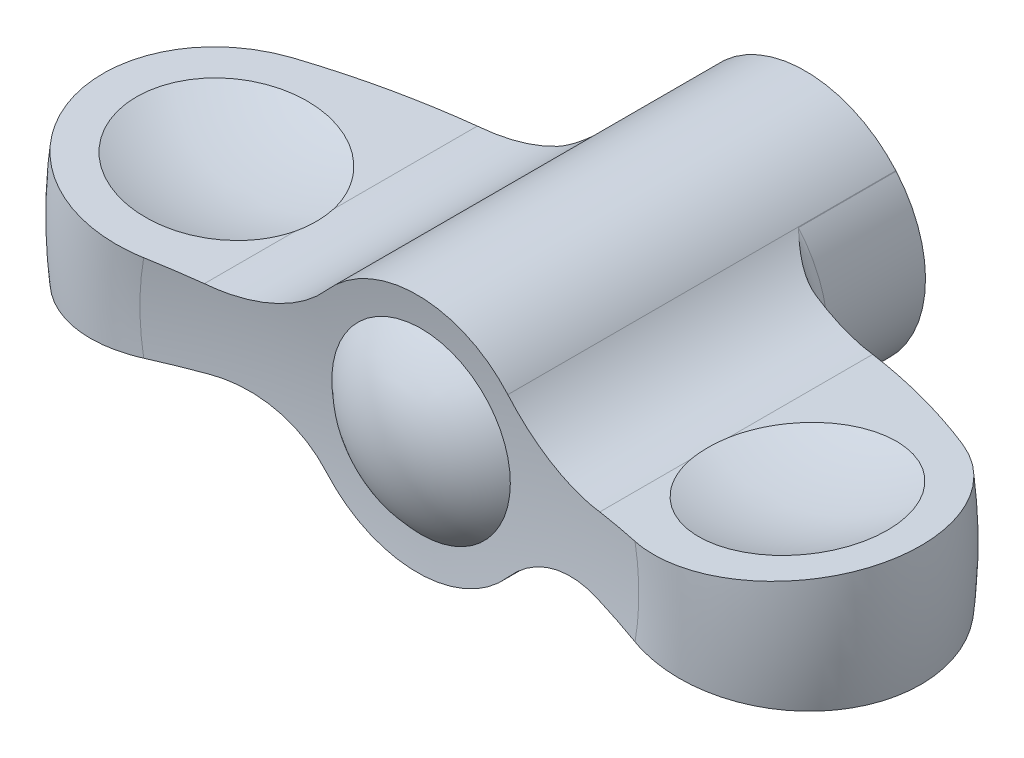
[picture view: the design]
ISO-10303-21;
HEADER;
FILE_DESCRIPTION(('STEP AP214'),'2;1');
FILE_NAME('part.step','',(''),(''),'','','');
FILE_SCHEMA(('AUTOMOTIVE_DESIGN { 1 0 10303 214 1 1 1 1 }'));
ENDSEC;
DATA;
#1=APPLICATION_CONTEXT('core data for automotive mechanical design processes');
#2=APPLICATION_PROTOCOL_DEFINITION('international standard','automotive_design',2000,#1);
#3=PRODUCT_CONTEXT('',#1,'mechanical');
#4=PRODUCT('Part','Part','',(#3));
#5=PRODUCT_RELATED_PRODUCT_CATEGORY('part','',(#4));
#6=PRODUCT_DEFINITION_FORMATION('','',#4);
#7=PRODUCT_DEFINITION_CONTEXT('part definition',#1,'design');
#8=PRODUCT_DEFINITION('design','',#6,#7);
#9=PRODUCT_DEFINITION_SHAPE('','',#8);
#10=(LENGTH_UNIT() NAMED_UNIT(*) SI_UNIT(.MILLI.,.METRE.));
#11=(NAMED_UNIT(*) PLANE_ANGLE_UNIT() SI_UNIT($,.RADIAN.));
#12=(NAMED_UNIT(*) SI_UNIT($,.STERADIAN.) SOLID_ANGLE_UNIT());
#13=UNCERTAINTY_MEASURE_WITH_UNIT(LENGTH_MEASURE(1.E-05),#10,'distance_accuracy_value','');
#14=(GEOMETRIC_REPRESENTATION_CONTEXT(3) GLOBAL_UNCERTAINTY_ASSIGNED_CONTEXT((#13)) GLOBAL_UNIT_ASSIGNED_CONTEXT((#10,
#11,#12)) REPRESENTATION_CONTEXT('',''));
#15=CARTESIAN_POINT('',(0.,0.,0.));
#16=DIRECTION('',(0.,0.,1.));
#17=DIRECTION('',(1.,0.,0.));
#18=AXIS2_PLACEMENT_3D('',#15,#16,#17);
#19=CARTESIAN_POINT('',(0.,0.,6.5));
#20=DIRECTION('',(0.,0.,1.));
#21=DIRECTION('',(0.,-1.,0.));
#22=AXIS2_PLACEMENT_3D('',#19,#20,#21);
#23=TOROIDAL_SURFACE('',#22,9.4,1.40000000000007);
#24=DIRECTION('',(0.,0.,1.));
#25=VECTOR('',#24,1.);
#26=CARTESIAN_POINT('',(6.03890778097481,-5.2470556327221,-7.02196379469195));
#27=LINE('',#26,#25);
#28=CARTESIAN_POINT('',(6.03890778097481,-5.24705563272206,6.5));
#29=VERTEX_POINT('',#28);
#30=CARTESIAN_POINT('',(6.03890778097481,-5.2470556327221,6.5021200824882));
#31=VERTEX_POINT('',#30);
#32=EDGE_CURVE('E174',#29,#31,#27,.T.);
#33=ORIENTED_EDGE('',*,*,#32,.F.);
#34=CARTESIAN_POINT('',(0.,0.,6.5));
#35=DIRECTION('',(0.,0.,1.));
#36=DIRECTION('',(0.,-1.,0.));
#37=AXIS2_PLACEMENT_3D('',#34,#35,#36);
#38=CIRCLE('',#37,8.);
#39=CARTESIAN_POINT('',(6.0470062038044,5.23772049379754,6.4999999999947));
#40=VERTEX_POINT('',#39);
#41=EDGE_CURVE('E415',#29,#40,#38,.T.);
#42=ORIENTED_EDGE('',*,*,#41,.T.);
#43=CARTESIAN_POINT('',(8.59708199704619,3.29504177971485,7.88661989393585));
#44=CARTESIAN_POINT('',(8.50944178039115,3.33729136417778,7.87729621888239));
#45=CARTESIAN_POINT('',(8.42307614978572,3.38091432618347,7.86348310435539));
#46=CARTESIAN_POINT('',(8.25334791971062,3.47048341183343,7.82827393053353));
#47=CARTESIAN_POINT('',(8.16997966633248,3.51642472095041,7.80689307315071));
#48=CARTESIAN_POINT('',(8.006927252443,3.6100455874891,7.75806975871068));
#49=CARTESIAN_POINT('',(7.92722117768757,3.65771052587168,7.73067131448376));
#50=CARTESIAN_POINT('',(7.77086822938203,3.75487699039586,7.67078020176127));
#51=CARTESIAN_POINT('',(7.69422278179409,3.80437935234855,7.6382851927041));
#52=CARTESIAN_POINT('',(7.51481068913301,3.9245724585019,7.55570149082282));
#53=CARTESIAN_POINT('',(7.41345025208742,3.996030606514,7.50367899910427));
#54=CARTESIAN_POINT('',(7.21620642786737,4.14190058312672,7.39355525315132));
#55=CARTESIAN_POINT('',(7.12032815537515,4.21631506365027,7.33544846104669));
#56=CARTESIAN_POINT('',(6.89765495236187,4.39723051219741,7.19147911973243));
#57=CARTESIAN_POINT('',(6.77323076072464,4.50501816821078,7.10356810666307));
#58=CARTESIAN_POINT('',(6.57394920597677,4.68848676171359,6.95337103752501));
#59=CARTESIAN_POINT('',(6.49659267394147,4.7626588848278,6.89250585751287));
#60=CARTESIAN_POINT('',(6.37240043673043,4.8865809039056,6.79132557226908));
#61=CARTESIAN_POINT('',(6.32451434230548,4.93561192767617,6.75141880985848));
#62=CARTESIAN_POINT('',(6.24744938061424,5.01656740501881,6.68590586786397));
#63=CARTESIAN_POINT('',(6.21784284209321,5.04817964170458,6.66041557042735));
#64=CARTESIAN_POINT('',(6.1701203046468,5.09997024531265,6.61881307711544));
#65=CARTESIAN_POINT('',(6.15183084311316,5.12002285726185,6.60274326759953));
#66=CARTESIAN_POINT('',(6.12231217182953,5.15271930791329,6.57655539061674));
#67=CARTESIAN_POINT('',(6.11100884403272,5.16531979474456,6.56646663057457));
#68=CARTESIAN_POINT('',(6.09275021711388,5.18580384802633,6.549990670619));
#69=CARTESIAN_POINT('',(6.08575717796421,5.19368060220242,6.54363714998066));
#70=CARTESIAN_POINT('',(6.07446460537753,5.20645064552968,6.53319636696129));
#71=CARTESIAN_POINT('',(6.07013806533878,5.21135545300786,6.52915239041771));
#72=CARTESIAN_POINT('',(6.06316395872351,5.21928103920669,6.52242537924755));
#73=CARTESIAN_POINT('',(6.06049083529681,5.22232358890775,6.51979601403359));
#74=CARTESIAN_POINT('',(6.05620285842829,5.22721145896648,6.51533355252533));
#75=CARTESIAN_POINT('',(6.05455913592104,5.22908696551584,6.51356171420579));
#76=CARTESIAN_POINT('',(6.05194270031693,5.23207504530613,6.51046552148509));
#77=CARTESIAN_POINT('',(6.05093886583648,5.23322217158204,6.50920550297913));
#78=CARTESIAN_POINT('',(6.04952852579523,5.23483466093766,6.50714224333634));
#79=CARTESIAN_POINT('',(6.04907130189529,5.23535757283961,6.50641962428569));
#80=CARTESIAN_POINT('',(6.04823146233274,5.23631829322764,6.50488003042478));
#81=CARTESIAN_POINT('',(6.04784824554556,5.23675678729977,6.50406390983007));
#82=CARTESIAN_POINT('',(6.04743475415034,5.2372299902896,6.50282878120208));
#83=CARTESIAN_POINT('',(6.04733123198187,5.23734847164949,6.50246832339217));
#84=CARTESIAN_POINT('',(6.04716301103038,5.23754100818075,6.50172769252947));
#85=CARTESIAN_POINT('',(6.04709815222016,5.23761524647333,6.50134760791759));
#86=CARTESIAN_POINT('',(6.04703697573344,5.23768527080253,6.50077037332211));
#87=CARTESIAN_POINT('',(6.04702259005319,5.23770173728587,6.50057747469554));
#88=CARTESIAN_POINT('',(6.0470060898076,5.23772062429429,6.50018965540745));
#89=CARTESIAN_POINT('',(6.04700402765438,5.23772298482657,6.49999472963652));
#90=CARTESIAN_POINT('',(6.0470084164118,5.23771796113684,6.49979999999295));
#91=B_SPLINE_CURVE_WITH_KNOTS('',3,(#43,#44,#45,#46,#47,#48,#49,#50,#51,#52,#53,#54,#55,#56,#57,
#58,#59,#60,#61,#62,#63,#64,#65,#66,#67,#68,#69,#70,#71,#72,#73,#74,#75,#76,#77,#78,#79,#80,#81,
#82,#83,#84,#85,#86,#87,#88,#89,#90),.UNSPECIFIED.,.F.,.F.,(4,2,2,2,2,2,2,2,2,2,2,2,2,2,2,2,2,2,
2,2,2,2,2,4),(0.,0.292919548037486,0.585253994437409,0.875517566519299,1.16591483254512,
1.56900991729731,1.97247513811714,2.53185645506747,2.90152662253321,3.1394263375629,
3.29018867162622,3.38481100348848,3.44392835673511,3.48083041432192,3.50389909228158,
3.51838177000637,3.52755772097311,3.53347737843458,3.53648190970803,3.53946090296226,
3.54063718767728,3.54180856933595,3.54239014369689,3.5429741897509),.UNSPECIFIED.);
#92=CARTESIAN_POINT('',(8.59520200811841,3.29594858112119,7.88641989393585));
#93=VERTEX_POINT('',#92);
#94=EDGE_CURVE('E383',#93,#40,#91,.T.);
#95=ORIENTED_EDGE('',*,*,#94,.F.);
#96=CARTESIAN_POINT('',(0.,0.,7.88641989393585));
#97=DIRECTION('',(0.,0.,1.));
#98=DIRECTION('',(0.,-1.,0.));
#99=AXIS2_PLACEMENT_3D('',#96,#97,#98);
#100=CIRCLE('',#99,9.20547525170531);
#101=CARTESIAN_POINT('',(8.59545916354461,-3.29527789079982,7.88641989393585));
#102=VERTEX_POINT('',#101);
#103=EDGE_CURVE('E411',#102,#93,#100,.T.);
#104=ORIENTED_EDGE('',*,*,#103,.F.);
#105=CARTESIAN_POINT('',(9.2464198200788,-3.01597169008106,7.86154869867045));
#106=CARTESIAN_POINT('',(9.191703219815,-3.03662617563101,7.87246212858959));
#107=CARTESIAN_POINT('',(9.13683292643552,-3.05803382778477,7.88088984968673));
#108=CARTESIAN_POINT('',(9.0272184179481,-3.10220967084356,7.89317258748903));
#109=CARTESIAN_POINT('',(8.97247413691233,-3.12497578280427,7.89703441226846));
#110=CARTESIAN_POINT('',(8.80995844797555,-3.19470660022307,7.90236716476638));
#111=CARTESIAN_POINT('',(8.70276195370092,-3.24353448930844,7.89779252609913));
#112=CARTESIAN_POINT('',(8.51047394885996,-3.33625869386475,7.87741400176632));
#113=CARTESIAN_POINT('',(8.42481297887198,-3.37951008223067,7.86372857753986));
#114=CARTESIAN_POINT('',(8.25627111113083,-3.46839491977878,7.82888132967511));
#115=CARTESIAN_POINT('',(8.17339149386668,-3.51402944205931,7.80771611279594));
#116=CARTESIAN_POINT('',(7.92832133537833,-3.65460006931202,7.73466741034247));
#117=CARTESIAN_POINT('',(7.77073045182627,-3.75270198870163,7.67337075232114));
#118=CARTESIAN_POINT('',(7.51219223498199,-3.92592329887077,7.55434149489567));
#119=CARTESIAN_POINT('',(7.40810830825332,-3.99942155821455,7.50076399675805));
#120=CARTESIAN_POINT('',(7.20573498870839,-4.14951628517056,7.38724676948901));
#121=CARTESIAN_POINT('',(7.10744753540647,-4.22611377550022,7.32730492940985));
#122=CARTESIAN_POINT('',(6.91648045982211,-4.38209339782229,7.20294133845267));
#123=CARTESIAN_POINT('',(6.82379096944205,-4.46147021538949,7.13852792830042));
#124=CARTESIAN_POINT('',(6.64338510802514,-4.62314447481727,7.00654560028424));
#125=CARTESIAN_POINT('',(6.55566785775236,-4.70544139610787,6.93897724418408));
#126=CARTESIAN_POINT('',(6.43300905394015,-4.82577735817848,6.84059313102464));
#127=CARTESIAN_POINT('',(6.39621820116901,-4.86258512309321,6.8105538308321));
#128=CARTESIAN_POINT('',(6.32347498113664,-4.93679114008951,6.75019039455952));
#129=CARTESIAN_POINT('',(6.28752259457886,-4.97418937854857,6.71986626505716));
#130=CARTESIAN_POINT('',(6.23420044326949,-5.03074553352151,6.67427938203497));
#131=CARTESIAN_POINT('',(6.21653276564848,-5.04966820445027,6.65907163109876));
#132=CARTESIAN_POINT('',(6.18141428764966,-5.08764734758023,6.62856921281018));
#133=CARTESIAN_POINT('',(6.16396349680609,-5.10670382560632,6.61327454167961));
#134=CARTESIAN_POINT('',(6.12918837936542,-5.14505447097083,6.58285648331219));
#135=CARTESIAN_POINT('',(6.11186402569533,-5.16434858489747,6.5677330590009));
#136=CARTESIAN_POINT('',(6.07769243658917,-5.20276831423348,6.53674407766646));
#137=CARTESIAN_POINT('',(6.06084502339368,-5.22189399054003,6.52087880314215));
#138=CARTESIAN_POINT('',(6.04125233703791,-5.24436286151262,6.50407138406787));
#139=CARTESIAN_POINT('',(6.03883132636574,-5.24714312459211,6.5020224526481));
#140=CARTESIAN_POINT('',(6.036402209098,-5.24993655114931,6.5));
#141=B_SPLINE_CURVE_WITH_KNOTS('',3,(#105,#106,#107,#108,#109,#110,#111,#112,#113,#114,#115,
#116,#117,#118,#119,#120,#121,#122,#123,#124,#125,#126,#127,#128,#129,#130,#131,#132,#133,#134,
#135,#136,#137,#138,#139,#140),.UNSPECIFIED.,.F.,.F.,(4,2,2,2,2,2,2,2,2,2,2,2,2,2,2,2,2,4),(0.,
0.178341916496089,0.356417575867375,0.708892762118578,0.999321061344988,1.28988128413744,
1.87442815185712,2.28884312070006,2.7033959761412,3.11719533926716,3.53092130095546,
3.71118323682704,3.89144102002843,3.98151493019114,4.07159278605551,4.16165075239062,
4.25167469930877,4.26432797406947),.UNSPECIFIED.);
#142=EDGE_CURVE('E353',#31,#102,#141,.F.);
#143=ORIENTED_EDGE('',*,*,#142,.F.);
#144=EDGE_LOOP('',(#33,#42,#95,#104,#143));
#145=FACE_BOUND('',#144,.T.);
#146=ADVANCED_FACE('F14',(#145),#23,.F.);
#147=CARTESIAN_POINT('',(7.9999999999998,0.,0.));
#148=DIRECTION('',(0.,0.,-1.));
#149=DIRECTION('',(0.,1.,0.));
#150=AXIS2_PLACEMENT_3D('',#147,#148,#149);
#151=PLANE('',#150);
#152=CARTESIAN_POINT('',(0.,0.,0.));
#153=DIRECTION('',(0.,0.,1.));
#154=DIRECTION('',(0.,-1.,0.));
#155=AXIS2_PLACEMENT_3D('',#152,#153,#154);
#156=CIRCLE('',#155,3.);
#157=CARTESIAN_POINT('',(0.,-3.,0.));
#158=VERTEX_POINT('',#157);
#159=EDGE_CURVE('E422',#158,#158,#156,.T.);
#160=ORIENTED_EDGE('',*,*,#159,.T.);
#161=EDGE_LOOP('',(#160));
#162=FACE_BOUND('',#161,.T.);
#163=CARTESIAN_POINT('',(12.0717114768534,10.5010774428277,0.));
#164=DIRECTION('',(0.,0.,-1.));
#165=DIRECTION('',(0.,1.,0.));
#166=AXIS2_PLACEMENT_3D('',#163,#164,#165);
#167=CIRCLE('',#166,8.);
#168=CARTESIAN_POINT('',(6.0470062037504,5.23772049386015,0.));
#169=VERTEX_POINT('',#168);
#170=CARTESIAN_POINT('',(6.02470527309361,5.26335694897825,0.));
#171=VERTEX_POINT('',#170);
#172=EDGE_CURVE('E264',#169,#171,#167,.T.);
#173=ORIENTED_EDGE('',*,*,#172,.F.);
#174=CARTESIAN_POINT('',(0.,0.,0.));
#175=DIRECTION('',(0.,0.,1.));
#176=DIRECTION('',(0.,-1.,0.));
#177=AXIS2_PLACEMENT_3D('',#174,#175,#176);
#178=CIRCLE('',#177,8.);
#179=CARTESIAN_POINT('',(-6.04700620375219,5.23772049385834,0.));
#180=VERTEX_POINT('',#179);
#181=EDGE_CURVE('E419',#180,#169,#178,.T.);
#182=ORIENTED_EDGE('',*,*,#181,.F.);
#183=CARTESIAN_POINT('',(-12.0717114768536,10.5010774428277,0.));
#184=DIRECTION('',(0.,0.,-1.));
#185=DIRECTION('',(0.,1.,0.));
#186=AXIS2_PLACEMENT_3D('',#183,#184,#185);
#187=CIRCLE('',#186,8.);
#188=CARTESIAN_POINT('',(-6.0247052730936,5.26335694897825,0.));
#189=VERTEX_POINT('',#188);
#190=EDGE_CURVE('E459',#180,#189,#187,.F.);
#191=ORIENTED_EDGE('',*,*,#190,.T.);
#192=EDGE_CURVE('E418',#171,#189,#178,.T.);
#193=ORIENTED_EDGE('',*,*,#192,.F.);
#194=EDGE_LOOP('',(#173,#182,#191,#193));
#195=FACE_BOUND('',#194,.T.);
#196=ADVANCED_FACE('F375',(#162,#195),#151,.T.);
#197=CARTESIAN_POINT('',(0.,0.,32.9780362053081));
#198=DIRECTION('',(0.,0.,1.));
#199=DIRECTION('',(0.,-1.,0.));
#200=AXIS2_PLACEMENT_3D('',#197,#198,#199);
#201=CYLINDRICAL_SURFACE('',#200,8.);
#202=DIRECTION('',(0.,0.,1.));
#203=VECTOR('',#202,1.);
#204=CARTESIAN_POINT('',(-6.0247052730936,5.26335694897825,-7.02196379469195));
#205=LINE('',#204,#203);
#206=CARTESIAN_POINT('',(-6.0247052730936,5.26335694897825,25.8131362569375));
#207=VERTEX_POINT('',#206);
#208=EDGE_CURVE('E158',#189,#207,#205,.T.);
#209=ORIENTED_EDGE('',*,*,#208,.T.);
#210=CARTESIAN_POINT('',(0.,0.,25.8131362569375));
#211=DIRECTION('',(0.,0.,1.));
#212=DIRECTION('',(0.,-1.,0.));
#213=AXIS2_PLACEMENT_3D('',#210,#211,#212);
#214=CIRCLE('',#213,8.);
#215=CARTESIAN_POINT('',(6.02470527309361,5.26335694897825,25.8131362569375));
#216=VERTEX_POINT('',#215);
#217=EDGE_CURVE('E269',#216,#207,#214,.T.);
#218=ORIENTED_EDGE('',*,*,#217,.F.);
#219=DIRECTION('',(0.,0.,1.));
#220=VECTOR('',#219,1.);
#221=CARTESIAN_POINT('',(6.02470527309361,5.26335694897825,-7.02196379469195));
#222=LINE('',#221,#220);
#223=EDGE_CURVE('E161',#171,#216,#222,.T.);
#224=ORIENTED_EDGE('',*,*,#223,.F.);
#225=ORIENTED_EDGE('',*,*,#192,.T.);
#226=EDGE_LOOP('',(#209,#218,#224,#225));
#227=FACE_BOUND('',#226,.T.);
#228=ADVANCED_FACE('F270',(#227),#201,.T.);
#229=DIRECTION('',(0.,0.,1.));
#230=VECTOR('',#229,1.);
#231=CARTESIAN_POINT('',(-6.04700620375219,5.23772049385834,3.25));
#232=LINE('',#231,#230);
#233=CARTESIAN_POINT('',(-6.04700620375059,5.23772049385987,6.5));
#234=VERTEX_POINT('',#233);
#235=EDGE_CURVE('E456',#180,#234,#232,.T.);
#236=ORIENTED_EDGE('',*,*,#235,.F.);
#237=ORIENTED_EDGE('',*,*,#181,.T.);
#238=DIRECTION('',(0.,0.,1.));
#239=VECTOR('',#238,1.);
#240=CARTESIAN_POINT('',(6.0470062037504,5.23772049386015,3.25));
#241=LINE('',#240,#239);
#242=EDGE_CURVE('E390',#169,#40,#241,.T.);
#243=ORIENTED_EDGE('',*,*,#242,.T.);
#244=ORIENTED_EDGE('',*,*,#41,.F.);
#245=ORIENTED_EDGE('',*,*,#32,.T.);
#246=CARTESIAN_POINT('',(6.03890778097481,-5.2470556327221,25.8131362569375));
#247=VERTEX_POINT('',#246);
#248=EDGE_CURVE('E171',#31,#247,#27,.T.);
#249=ORIENTED_EDGE('',*,*,#248,.T.);
#250=CARTESIAN_POINT('',(0.,0.,25.8131362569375));
#251=DIRECTION('',(0.,0.,1.));
#252=DIRECTION('',(0.,-1.,0.));
#253=AXIS2_PLACEMENT_3D('',#250,#251,#252);
#254=CIRCLE('',#253,8.);
#255=CARTESIAN_POINT('',(-6.0389077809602,-5.24705563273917,25.8131362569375));
#256=VERTEX_POINT('',#255);
#257=EDGE_CURVE('E329',#256,#247,#254,.T.);
#258=ORIENTED_EDGE('',*,*,#257,.F.);
#259=DIRECTION('',(0.,0.,1.));
#260=VECTOR('',#259,1.);
#261=CARTESIAN_POINT('',(-6.03890778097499,-5.2470556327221,-7.02196379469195));
#262=LINE('',#261,#260);
#263=CARTESIAN_POINT('',(-6.03890778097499,-5.2470556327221,6.5021200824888));
#264=VERTEX_POINT('',#263);
#265=EDGE_CURVE('E167',#264,#256,#262,.T.);
#266=ORIENTED_EDGE('',*,*,#265,.F.);
#267=CARTESIAN_POINT('',(-6.03890778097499,-5.24705563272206,6.5));
#268=VERTEX_POINT('',#267);
#269=EDGE_CURVE('E170',#268,#264,#262,.T.);
#270=ORIENTED_EDGE('',*,*,#269,.F.);
#271=EDGE_CURVE('E414',#234,#268,#38,.T.);
#272=ORIENTED_EDGE('',*,*,#271,.F.);
#273=EDGE_LOOP('',(#236,#237,#243,#244,#245,#249,#258,#266,#270,#272));
#274=FACE_BOUND('',#273,.T.);
#275=ADVANCED_FACE('F447',(#274),#201,.T.);
#276=ORIENTED_EDGE('',*,*,#271,.T.);
#277=ORIENTED_EDGE('',*,*,#269,.T.);
#278=CARTESIAN_POINT('',(-9.246419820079,-3.01597169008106,7.86154869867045));
#279=CARTESIAN_POINT('',(-9.19170321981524,-3.03662617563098,7.87246212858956));
#280=CARTESIAN_POINT('',(-9.1368329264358,-3.05803382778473,7.88088984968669));
#281=CARTESIAN_POINT('',(-9.02721841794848,-3.10220967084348,7.89317258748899));
#282=CARTESIAN_POINT('',(-8.97247413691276,-3.12497578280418,7.89703441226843));
#283=CARTESIAN_POINT('',(-8.80995844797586,-3.19470660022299,7.9023671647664));
#284=CARTESIAN_POINT('',(-8.70276195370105,-3.24353448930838,7.89779252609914));
#285=CARTESIAN_POINT('',(-8.51047394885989,-3.33625869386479,7.87741400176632));
#286=CARTESIAN_POINT('',(-8.42481297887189,-3.37951008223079,7.86372857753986));
#287=CARTESIAN_POINT('',(-8.25627111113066,-3.46839491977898,7.82888132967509));
#288=CARTESIAN_POINT('',(-8.17339149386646,-3.51402944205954,7.80771611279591));
#289=CARTESIAN_POINT('',(-7.92832133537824,-3.65460006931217,7.73466741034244));
#290=CARTESIAN_POINT('',(-7.77073045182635,-3.75270198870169,7.67337075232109));
#291=CARTESIAN_POINT('',(-7.51219223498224,-3.92592329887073,7.55434149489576));
#292=CARTESIAN_POINT('',(-7.40810830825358,-3.99942155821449,7.50076399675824));
#293=CARTESIAN_POINT('',(-7.20573498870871,-4.14951628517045,7.38724676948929));
#294=CARTESIAN_POINT('',(-7.10744753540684,-4.22611377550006,7.32730492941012));
#295=CARTESIAN_POINT('',(-6.91648045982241,-4.38209339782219,7.20294133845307));
#296=CARTESIAN_POINT('',(-6.82379096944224,-4.46147021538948,7.13852792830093));
#297=CARTESIAN_POINT('',(-6.64338510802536,-4.62314447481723,7.00654560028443));
#298=CARTESIAN_POINT('',(-6.5556678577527,-4.7054413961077,6.93897724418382));
#299=CARTESIAN_POINT('',(-6.43300905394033,-4.82577735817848,6.84059313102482));
#300=CARTESIAN_POINT('',(-6.39621820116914,-4.86258512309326,6.81055383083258));
#301=CARTESIAN_POINT('',(-6.3234749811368,-4.93679114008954,6.75019039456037));
#302=CARTESIAN_POINT('',(-6.28752259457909,-4.97418937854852,6.71986626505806));
#303=CARTESIAN_POINT('',(-6.23420044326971,-5.03074553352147,6.6742793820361));
#304=CARTESIAN_POINT('',(-6.21653276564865,-5.04966820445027,6.65907163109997));
#305=CARTESIAN_POINT('',(-6.18141428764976,-5.08764734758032,6.62856921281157));
#306=CARTESIAN_POINT('',(-6.16396349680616,-5.10670382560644,6.61327454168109));
#307=CARTESIAN_POINT('',(-6.12918837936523,-5.14505447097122,6.58285648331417));
#308=CARTESIAN_POINT('',(-6.11186402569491,-5.1643485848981,6.56773305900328));
#309=CARTESIAN_POINT('',(-6.07769243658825,-5.20276831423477,6.53674407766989));
#310=CARTESIAN_POINT('',(-6.06084502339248,-5.22189399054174,6.52087880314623));
#311=CARTESIAN_POINT('',(-6.04125233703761,-5.24436286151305,6.50407138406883));
#312=CARTESIAN_POINT('',(-6.03883132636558,-5.24714312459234,6.50202245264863));
#313=CARTESIAN_POINT('',(-6.036402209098,-5.2499365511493,6.5));
#314=B_SPLINE_CURVE_WITH_KNOTS('',3,(#278,#279,#280,#281,#282,#283,#284,#285,#286,#287,#288,
#289,#290,#291,#292,#293,#294,#295,#296,#297,#298,#299,#300,#301,#302,#303,#304,#305,#306,#307,
#308,#309,#310,#311,#312,#313),.UNSPECIFIED.,.F.,.F.,(4,2,2,2,2,2,2,2,2,2,2,2,2,2,2,2,2,4),(0.,
0.178341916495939,0.356417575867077,0.708892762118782,0.999321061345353,1.28988128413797,
1.8744281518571,2.28884312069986,2.70339597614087,3.11719533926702,3.53092130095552,
3.71118323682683,3.89144102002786,3.98151493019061,4.07159278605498,4.16165075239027,
4.25167469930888,4.2643279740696),.UNSPECIFIED.);
#315=CARTESIAN_POINT('',(-8.59545916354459,-3.29527789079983,7.88641989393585));
#316=VERTEX_POINT('',#315);
#317=EDGE_CURVE('E354',#264,#316,#314,.F.);
#318=ORIENTED_EDGE('',*,*,#317,.T.);
#319=CARTESIAN_POINT('',(-8.5952020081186,3.29594858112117,7.88641989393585));
#320=VERTEX_POINT('',#319);
#321=EDGE_CURVE('E410',#320,#316,#100,.T.);
#322=ORIENTED_EDGE('',*,*,#321,.F.);
#323=CARTESIAN_POINT('',(-8.59708199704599,3.29504177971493,7.88661989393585));
#324=CARTESIAN_POINT('',(-8.50944178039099,3.33729136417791,7.87729621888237));
#325=CARTESIAN_POINT('',(-8.42307614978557,3.38091432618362,7.86348310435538));
#326=CARTESIAN_POINT('',(-8.25334791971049,3.47048341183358,7.82827393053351));
#327=CARTESIAN_POINT('',(-8.16997966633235,3.51642472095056,7.80689307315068));
#328=CARTESIAN_POINT('',(-8.00692725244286,3.61004558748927,7.75806975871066));
#329=CARTESIAN_POINT('',(-7.92722117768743,3.65771052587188,7.73067131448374));
#330=CARTESIAN_POINT('',(-7.77086822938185,3.75487699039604,7.67078020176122));
#331=CARTESIAN_POINT('',(-7.69422278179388,3.80437935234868,7.63828519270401));
#332=CARTESIAN_POINT('',(-7.51481068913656,3.92457245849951,7.55570149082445));
#333=CARTESIAN_POINT('',(-7.41345025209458,3.99603060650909,7.50367899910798));
#334=CARTESIAN_POINT('',(-7.21620642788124,4.14190058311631,7.39355525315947));
#335=CARTESIAN_POINT('',(-7.12032815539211,4.2163150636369,7.33544846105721));
#336=CARTESIAN_POINT('',(-6.8976549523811,4.39723051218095,7.19147911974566));
#337=CARTESIAN_POINT('',(-6.77323076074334,4.50501816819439,7.1035681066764));
#338=CARTESIAN_POINT('',(-6.57394920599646,4.68848676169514,6.95337103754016));
#339=CARTESIAN_POINT('',(-6.49659267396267,4.76265888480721,6.89250585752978));
#340=CARTESIAN_POINT('',(-6.37240043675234,4.88658090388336,6.7913255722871));
#341=CARTESIAN_POINT('',(-6.32451434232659,4.93561192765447,6.7514188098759));
#342=CARTESIAN_POINT('',(-6.24744938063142,5.01656740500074,6.68590586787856));
#343=CARTESIAN_POINT('',(-6.21784284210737,5.04817964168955,6.66041557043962));
#344=CARTESIAN_POINT('',(-6.17012030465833,5.09997024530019,6.61881307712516));
#345=CARTESIAN_POINT('',(-6.1518308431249,5.12002285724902,6.60274326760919));
#346=CARTESIAN_POINT('',(-6.12231217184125,5.15271930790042,6.57655539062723));
#347=CARTESIAN_POINT('',(-6.11100884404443,5.16531979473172,6.56646663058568));
#348=CARTESIAN_POINT('',(-6.09275021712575,5.1858038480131,6.54999067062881));
#349=CARTESIAN_POINT('',(-6.08575717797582,5.19368060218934,6.54363714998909));
#350=CARTESIAN_POINT('',(-6.07446460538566,5.20645064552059,6.53319636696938));
#351=CARTESIAN_POINT('',(-6.07013806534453,5.21135545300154,6.52915239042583));
#352=CARTESIAN_POINT('',(-6.06316395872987,5.21928103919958,6.52242537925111));
#353=CARTESIAN_POINT('',(-6.06049083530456,5.22232358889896,6.51979601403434));
#354=CARTESIAN_POINT('',(-6.05620285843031,5.22721145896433,6.51533355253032));
#355=CARTESIAN_POINT('',(-6.05455913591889,5.22908696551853,6.51356171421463));
#356=CARTESIAN_POINT('',(-6.05194270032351,5.23207504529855,6.51046552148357));
#357=CARTESIAN_POINT('',(-6.05093886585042,5.23322217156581,6.50920550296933));
#358=CARTESIAN_POINT('',(-6.04952852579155,5.23483466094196,6.5071422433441));
#359=CARTESIAN_POINT('',(-6.0490713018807,5.23535757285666,6.50641962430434));
#360=CARTESIAN_POINT('',(-6.04823146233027,5.23631829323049,6.50488003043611));
#361=CARTESIAN_POINT('',(-6.04784824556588,5.23675678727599,6.50406390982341));
#362=CARTESIAN_POINT('',(-6.04743475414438,5.23722999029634,6.50282878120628));
#363=CARTESIAN_POINT('',(-6.04733123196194,5.23734847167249,6.50246832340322));
#364=CARTESIAN_POINT('',(-6.04716301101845,5.23754100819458,6.50172769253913));
#365=CARTESIAN_POINT('',(-6.04709815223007,5.23761524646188,6.50134760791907));
#366=CARTESIAN_POINT('',(-6.04703697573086,5.23768527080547,6.5007703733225));
#367=CARTESIAN_POINT('',(-6.04702259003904,5.23770173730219,6.50057747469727));
#368=CARTESIAN_POINT('',(-6.04700608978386,5.23772062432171,6.50018965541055));
#369=CARTESIAN_POINT('',(-6.04700402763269,5.23772298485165,6.49999472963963));
#370=CARTESIAN_POINT('',(-6.0470084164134,5.23771796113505,6.49979999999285));
#371=B_SPLINE_CURVE_WITH_KNOTS('',3,(#323,#324,#325,#326,#327,#328,#329,#330,#331,#332,#333,
#334,#335,#336,#337,#338,#339,#340,#341,#342,#343,#344,#345,#346,#347,#348,#349,#350,#351,#352,
#353,#354,#355,#356,#357,#358,#359,#360,#361,#362,#363,#364,#365,#366,#367,#368,#369,#370),
.UNSPECIFIED.,.F.,.F.,(4,2,2,2,2,2,2,2,2,2,2,2,2,2,2,2,2,2,2,2,2,2,2,4),(0.,0.292919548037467,
0.58525399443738,0.875517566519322,1.16591483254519,1.56900991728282,1.97247513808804,
2.53185645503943,2.90152662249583,3.13942633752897,3.29018867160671,3.38481100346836,
3.44392835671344,3.48083041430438,3.503899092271,3.51838176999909,3.52755772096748,
3.53347737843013,3.53648190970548,3.53946090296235,3.54063718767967,3.54180856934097,
3.54239014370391,3.54297418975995),.UNSPECIFIED.);
#372=EDGE_CURVE('E190',#320,#234,#371,.T.);
#373=ORIENTED_EDGE('',*,*,#372,.T.);
#374=EDGE_LOOP('',(#276,#277,#318,#322,#373));
#375=FACE_BOUND('',#374,.T.);
#376=ADVANCED_FACE('F377',(#375),#23,.F.);
#377=CARTESIAN_POINT('',(0.,0.,55.408674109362));
#378=DIRECTION('',(0.,0.,1.));
#379=DIRECTION('',(0.,-1.,0.));
#380=AXIS2_PLACEMENT_3D('',#377,#378,#379);
#381=DEGENERATE_TOROIDAL_SURFACE('',#380,2.53775894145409,47.9877389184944,.T.);
#382=ORIENTED_EDGE('',*,*,#103,.T.);
#383=CARTESIAN_POINT('',(5.40789714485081,6.07461400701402,7.74825077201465));
#384=CARTESIAN_POINT('',(5.5291773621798,5.89198502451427,7.7417150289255));
#385=CARTESIAN_POINT('',(5.65803975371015,5.71432205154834,7.7372582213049));
#386=CARTESIAN_POINT('',(5.92992964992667,5.37014226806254,7.7324895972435));
#387=CARTESIAN_POINT('',(6.07295642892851,5.2036248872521,7.73217756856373));
#388=CARTESIAN_POINT('',(6.37210580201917,4.88302009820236,7.73568398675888));
#389=CARTESIAN_POINT('',(6.52822111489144,4.72892587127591,7.73950015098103));
#390=CARTESIAN_POINT('',(6.85248447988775,4.43414479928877,7.75130368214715));
#391=CARTESIAN_POINT('',(7.02063240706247,4.29345781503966,7.75929100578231));
#392=CARTESIAN_POINT('',(7.36839276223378,4.02596374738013,7.77954568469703));
#393=CARTESIAN_POINT('',(7.54804576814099,3.89921061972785,7.79182895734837));
#394=CARTESIAN_POINT('',(7.9169239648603,3.66105266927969,7.82074605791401));
#395=CARTESIAN_POINT('',(8.10614934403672,3.54964814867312,7.83737997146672));
#396=CARTESIAN_POINT('',(8.49266533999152,3.34297499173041,7.87504105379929));
#397=CARTESIAN_POINT('',(8.68995161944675,3.24769781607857,7.89606588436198));
#398=CARTESIAN_POINT('',(9.09122637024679,3.07379499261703,7.94252339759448));
#399=CARTESIAN_POINT('',(9.29521479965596,2.99516924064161,7.96795605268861));
#400=CARTESIAN_POINT('',(9.70845663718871,2.854990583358,8.02319155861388));
#401=CARTESIAN_POINT('',(9.91771139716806,2.79344211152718,8.05299554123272));
#402=CARTESIAN_POINT('',(10.3400150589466,2.68771529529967,8.11688005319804));
#403=CARTESIAN_POINT('',(10.5530655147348,2.64354424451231,8.15096237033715));
#404=CARTESIAN_POINT('',(10.9815499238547,2.57272696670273,8.22326754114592));
#405=CARTESIAN_POINT('',(11.1969857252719,2.54609545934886,8.2614938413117));
#406=CARTESIAN_POINT('',(11.6284903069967,2.51043256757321,8.34184151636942));
#407=CARTESIAN_POINT('',(11.844558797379,2.50139409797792,8.38396131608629));
#408=CARTESIAN_POINT('',(12.2806577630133,2.50077046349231,8.47281848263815));
#409=CARTESIAN_POINT('',(12.5006723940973,2.50956853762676,8.51963625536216));
#410=CARTESIAN_POINT('',(12.9384709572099,2.54513800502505,8.6167995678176));
#411=CARTESIAN_POINT('',(13.156254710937,2.57191082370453,8.66714538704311));
#412=CARTESIAN_POINT('',(13.5879515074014,2.6430363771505,8.77098851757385));
#413=CARTESIAN_POINT('',(13.8018678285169,2.68737341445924,8.82448297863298));
#414=CARTESIAN_POINT('',(14.2246542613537,2.79313397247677,8.93430204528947));
#415=CARTESIAN_POINT('',(14.4335251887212,2.85455471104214,8.99062618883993));
#416=CARTESIAN_POINT('',(14.6392212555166,2.92427775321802,9.04819298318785));
#417=B_SPLINE_CURVE_WITH_KNOTS('',3,(#383,#384,#385,#386,#387,#388,#389,#390,#391,#392,#393,
#394,#395,#396,#397,#398,#399,#400,#401,#402,#403,#404,#405,#406,#407,#408,#409,#410,#411,#412,
#413,#414,#415,#416),.UNSPECIFIED.,.F.,.F.,(4,2,2,2,2,2,2,2,2,2,2,2,2,2,2,2,4),(0.,
0.657784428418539,1.31553517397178,1.9729224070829,2.63030281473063,3.2901452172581,
3.95000060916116,4.60950551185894,5.26900628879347,5.92867812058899,6.58862653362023,
7.24912809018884,7.90936359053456,8.58393530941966,9.25856052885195,9.93258417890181,
10.6064981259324),.UNSPECIFIED.);
#418=CARTESIAN_POINT('',(13.1528156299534,2.57446317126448,8.66701618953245));
#419=VERTEX_POINT('',#418);
#420=EDGE_CURVE('E391',#93,#419,#417,.T.);
#421=ORIENTED_EDGE('',*,*,#420,.T.);
#422=CARTESIAN_POINT('',(13.1526156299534,2.57444288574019,8.66696966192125));
#423=CARTESIAN_POINT('',(13.9370340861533,2.65400458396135,8.84943351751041));
#424=CARTESIAN_POINT('',(14.7168563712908,2.73310010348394,9.05185397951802));
#425=CARTESIAN_POINT('',(16.2633623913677,2.88995853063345,9.49546553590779));
#426=CARTESIAN_POINT('',(17.0300745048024,2.96772431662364,9.73655668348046));
#427=CARTESIAN_POINT('',(18.5504261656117,3.12192996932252,10.2573018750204));
#428=CARTESIAN_POINT('',(19.3040656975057,3.19836983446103,10.5369559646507));
#429=CARTESIAN_POINT('',(20.7982632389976,3.34992273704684,11.134858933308));
#430=CARTESIAN_POINT('',(21.5387829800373,3.4250318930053,11.4532044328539));
#431=CARTESIAN_POINT('',(22.2708092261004,3.49927957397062,11.7901956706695));
#432=B_SPLINE_CURVE_WITH_KNOTS('',3,(#422,#423,#424,#425,#426,#427,#428,#429,#430,#431),
.UNSPECIFIED.,.F.,.F.,(4,2,2,2,4),(0.,2.42758220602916,4.84898838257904,7.27039742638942,
9.69798251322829),.UNSPECIFIED.);
#433=CARTESIAN_POINT('',(22.2703747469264,3.49923550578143,11.7899956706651));
#434=VERTEX_POINT('',#433);
#435=EDGE_CURVE('E536',#419,#434,#432,.T.);
#436=ORIENTED_EDGE('',*,*,#435,.T.);
#437=CARTESIAN_POINT('',(0.,0.,11.7899956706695));
#438=DIRECTION('',(0.,0.,1.));
#439=DIRECTION('',(0.,-1.,0.));
#440=AXIS2_PLACEMENT_3D('',#437,#438,#439);
#441=CIRCLE('',#440,22.5436075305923);
#442=CARTESIAN_POINT('',(22.2706216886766,-3.49766351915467,11.7899956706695));
#443=VERTEX_POINT('',#442);
#444=EDGE_CURVE('E407',#443,#434,#441,.T.);
#445=ORIENTED_EDGE('',*,*,#444,.F.);
#446=CARTESIAN_POINT('',(12.9962083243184,-2.55398166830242,8.63065853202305));
#447=CARTESIAN_POINT('',(13.7943446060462,-2.63519292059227,8.81347846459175));
#448=CARTESIAN_POINT('',(14.5877985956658,-2.71592774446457,9.01694513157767));
#449=CARTESIAN_POINT('',(16.1611919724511,-2.87602226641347,9.46398142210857));
#450=CARTESIAN_POINT('',(16.9411614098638,-2.95538502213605,9.70744418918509));
#451=CARTESIAN_POINT('',(18.4876557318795,-3.11274253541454,10.2342505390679));
#452=CARTESIAN_POINT('',(19.2541805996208,-3.19073729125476,10.5175941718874));
#453=CARTESIAN_POINT('',(20.7737763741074,-3.34535784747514,11.1241962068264));
#454=CARTESIAN_POINT('',(21.5268064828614,-3.42197949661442,11.4475578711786));
#455=CARTESIAN_POINT('',(22.271056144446,-3.4977077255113,11.7901956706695));
#456=B_SPLINE_CURVE_WITH_KNOTS('',3,(#446,#447,#448,#449,#450,#451,#452,#453,#454,#455),
.UNSPECIFIED.,.F.,.F.,(4,2,2,2,4),(0.,2.46819948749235,4.92990890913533,7.3916214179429,
9.85982400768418),.UNSPECIFIED.);
#457=CARTESIAN_POINT('',(12.9964083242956,-2.5540020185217,8.63070434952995));
#458=VERTEX_POINT('',#457);
#459=EDGE_CURVE('E530',#458,#443,#456,.T.);
#460=ORIENTED_EDGE('',*,*,#459,.F.);
#461=CARTESIAN_POINT('',(5.40816196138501,-6.0746786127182,7.7482771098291));
#462=CARTESIAN_POINT('',(5.52938177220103,-5.89205626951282,7.74173743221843));
#463=CARTESIAN_POINT('',(5.65818351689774,-5.7143974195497,7.73727619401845));
#464=CARTESIAN_POINT('',(5.92995209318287,-5.37022086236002,7.73249766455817));
#465=CARTESIAN_POINT('',(6.07291819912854,-5.20370258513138,7.7321801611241));
#466=CARTESIAN_POINT('',(6.37194671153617,-4.88309096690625,7.73567453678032));
#467=CARTESIAN_POINT('',(6.52800183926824,-4.72899081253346,7.73948413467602));
#468=CARTESIAN_POINT('',(6.85214571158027,-4.43419295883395,7.75127335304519));
#469=CARTESIAN_POINT('',(7.02023433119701,-4.29349512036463,7.75925293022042));
#470=CARTESIAN_POINT('',(7.36787685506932,-4.02597472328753,7.77949081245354));
#471=CARTESIAN_POINT('',(7.54747132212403,-3.89920607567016,7.79176502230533));
#472=CARTESIAN_POINT('',(7.91623418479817,-3.66101233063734,7.82066267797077));
#473=CARTESIAN_POINT('',(8.10540276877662,-3.54958753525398,7.83728620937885));
#474=CARTESIAN_POINT('',(8.49180737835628,-3.34286928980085,7.87492522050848));
#475=CARTESIAN_POINT('',(8.68903906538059,-3.24756730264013,7.89593836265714));
#476=CARTESIAN_POINT('',(9.09020720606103,-3.0736105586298,7.94237123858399));
#477=CARTESIAN_POINT('',(9.29414361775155,-2.99495569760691,7.96779094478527));
#478=CARTESIAN_POINT('',(9.70728411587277,-2.85471488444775,8.02299934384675));
#479=CARTESIAN_POINT('',(9.91648954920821,-2.79313334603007,8.05278916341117));
#480=CARTESIAN_POINT('',(10.3386977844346,-2.68733665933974,8.11664426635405));
#481=CARTESIAN_POINT('',(10.5517021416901,-2.6431288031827,8.15071133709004));
#482=CARTESIAN_POINT('',(10.980097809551,-2.57223450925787,8.22298504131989));
#483=CARTESIAN_POINT('',(11.1954909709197,-2.5455627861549,8.26119511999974));
#484=CARTESIAN_POINT('',(11.6269140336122,-2.50981645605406,8.34150952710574));
#485=CARTESIAN_POINT('',(11.8429436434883,-2.5007347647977,8.38361228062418));
#486=CARTESIAN_POINT('',(12.2789655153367,-2.50002106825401,8.4724337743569));
#487=CARTESIAN_POINT('',(12.4989420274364,-2.50877204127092,8.51923286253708));
#488=CARTESIAN_POINT('',(12.9366686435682,-2.5442445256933,8.61635812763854));
#489=CARTESIAN_POINT('',(13.1544185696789,-2.57096746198,8.66668458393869));
#490=CARTESIAN_POINT('',(13.5860522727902,-2.6419909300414,8.77048849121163));
#491=CARTESIAN_POINT('',(13.7999393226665,-2.68627577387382,8.82396309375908));
#492=CARTESIAN_POINT('',(14.2226717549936,-2.79192997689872,8.93374204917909));
#493=CARTESIAN_POINT('',(14.4315179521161,-2.85329655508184,8.99004594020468));
#494=CARTESIAN_POINT('',(14.6371915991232,-2.92296463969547,9.04759234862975));
#495=B_SPLINE_CURVE_WITH_KNOTS('',3,(#461,#462,#463,#464,#465,#466,#467,#468,#469,#470,#471,
#472,#473,#474,#475,#476,#477,#478,#479,#480,#481,#482,#483,#484,#485,#486,#487,#488,#489,#490,
#491,#492,#493,#494),.UNSPECIFIED.,.F.,.F.,(4,2,2,2,2,2,2,2,2,2,2,2,2,2,2,2,4),(0.,
0.657668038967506,1.31530240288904,1.97257345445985,2.62983768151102,3.28956225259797,
3.9492998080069,4.60868692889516,5.26806992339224,5.92762322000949,6.58745305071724,
7.24783584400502,7.90795261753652,8.58239553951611,9.25689194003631,9.93078716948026,
10.6045727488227),.UNSPECIFIED.);
#496=EDGE_CURVE('E347',#458,#102,#495,.F.);
#497=ORIENTED_EDGE('',*,*,#496,.T.);
#498=EDGE_LOOP('',(#382,#421,#436,#445,#460,#497));
#499=FACE_BOUND('',#498,.T.);
#500=ADVANCED_FACE('F553',(#499),#381,.T.);
#501=CARTESIAN_POINT('',(0.,0.,19.5161101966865));
#502=DIRECTION('',(0.,0.,1.));
#503=DIRECTION('',(0.,-1.,0.));
#504=AXIS2_PLACEMENT_3D('',#501,#502,#503);
#505=TOROIDAL_SURFACE('',#504,19.,8.5);
#506=CARTESIAN_POINT('',(0.,0.,27.6698599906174));
#507=DIRECTION('',(0.,0.,1.));
#508=DIRECTION('',(0.,-1.,0.));
#509=AXIS2_PLACEMENT_3D('',#506,#507,#508);
#510=CIRCLE('',#509,16.5986744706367);
#511=CARTESIAN_POINT('',(16.3443249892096,-2.89465625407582,27.6698599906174));
#512=VERTEX_POINT('',#511);
#513=CARTESIAN_POINT('',(16.3437132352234,2.89810832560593,27.6698599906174));
#514=VERTEX_POINT('',#513);
#515=EDGE_CURVE('E404',#512,#514,#510,.T.);
#516=ORIENTED_EDGE('',*,*,#515,.F.);
#517=CARTESIAN_POINT('',(22.2701871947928,-3.49761930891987,11.7897956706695));
#518=CARTESIAN_POINT('',(22.4865890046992,-3.51963843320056,11.8893708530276));
#519=CARTESIAN_POINT('',(22.6987916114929,-3.54123028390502,11.9981566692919));
#520=CARTESIAN_POINT('',(23.1133331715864,-3.5834103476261,12.2332797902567));
#521=CARTESIAN_POINT('',(23.3156725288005,-3.60399860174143,12.359616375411));
#522=CARTESIAN_POINT('',(23.7089103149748,-3.64401098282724,12.6288905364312));
#523=CARTESIAN_POINT('',(23.8998162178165,-3.66343587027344,12.771817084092));
#524=CARTESIAN_POINT('',(24.2689734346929,-3.70099802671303,13.0733193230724));
#525=CARTESIAN_POINT('',(24.4472249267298,-3.71913531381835,13.2318947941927));
#526=CARTESIAN_POINT('',(24.7898897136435,-3.75400183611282,13.5636589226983));
#527=CARTESIAN_POINT('',(24.9542960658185,-3.77073036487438,13.7368548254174));
#528=CARTESIAN_POINT('',(25.2679995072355,-3.80265003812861,14.0965647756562));
#529=CARTESIAN_POINT('',(25.4172963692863,-3.81784115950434,14.2830790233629));
#530=CARTESIAN_POINT('',(25.6996801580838,-3.84657402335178,14.6680564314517));
#531=CARTESIAN_POINT('',(25.8327705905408,-3.86011612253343,14.8665169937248));
#532=CARTESIAN_POINT('',(26.0818270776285,-3.88545789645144,15.2740114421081));
#533=CARTESIAN_POINT('',(26.1977932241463,-3.89725758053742,15.4830452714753));
#534=CARTESIAN_POINT('',(26.4116662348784,-3.91901939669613,15.9099873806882));
#535=CARTESIAN_POINT('',(26.5095909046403,-3.92898334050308,16.1278866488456));
#536=CARTESIAN_POINT('',(26.6868542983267,-3.9470200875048,16.5712819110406));
#537=CARTESIAN_POINT('',(26.7661865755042,-3.95509223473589,16.7967805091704));
#538=CARTESIAN_POINT('',(26.9056523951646,-3.96928303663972,17.2536913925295));
#539=CARTESIAN_POINT('',(26.9657864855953,-3.97540174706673,17.4851035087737));
#540=CARTESIAN_POINT('',(27.0664298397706,-3.98564232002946,17.9522037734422));
#541=CARTESIAN_POINT('',(27.1069388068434,-3.98976415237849,18.1878919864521));
#542=CARTESIAN_POINT('',(27.1680180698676,-3.99597903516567,18.6616856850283));
#543=CARTESIAN_POINT('',(27.1886032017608,-3.99807359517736,18.8997892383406));
#544=CARTESIAN_POINT('',(27.2097404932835,-4.00022433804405,19.3768982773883));
#545=CARTESIAN_POINT('',(27.2102922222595,-4.00028047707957,19.6159037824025));
#546=CARTESIAN_POINT('',(27.1913600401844,-3.99835410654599,20.0930519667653));
#547=CARTESIAN_POINT('',(27.1718811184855,-3.99637210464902,20.331194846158));
#548=CARTESIAN_POINT('',(27.1130241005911,-3.99038333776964,20.8050668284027));
#549=CARTESIAN_POINT('',(27.0736391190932,-3.98637587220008,21.0407950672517));
#550=CARTESIAN_POINT('',(26.9752654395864,-3.97636624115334,21.5079930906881));
#551=CARTESIAN_POINT('',(26.9162837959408,-3.97036479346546,21.739464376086));
#552=CARTESIAN_POINT('',(26.7791326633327,-3.95640951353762,22.1965957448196));
#553=CARTESIAN_POINT('',(26.7009627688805,-3.94845564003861,22.4222557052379));
#554=CARTESIAN_POINT('',(26.5259936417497,-3.93065233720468,22.8661561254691));
#555=CARTESIAN_POINT('',(26.4291944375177,-3.92080291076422,23.0843965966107));
#556=CARTESIAN_POINT('',(26.2176548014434,-3.89927851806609,23.5119136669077));
#557=CARTESIAN_POINT('',(26.1029139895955,-3.88760351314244,23.7211900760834));
#558=CARTESIAN_POINT('',(25.8562793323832,-3.86250816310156,24.129341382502));
#559=CARTESIAN_POINT('',(25.7243811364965,-3.84908737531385,24.328213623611));
#560=CARTESIAN_POINT('',(25.4443947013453,-3.82059844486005,24.7140892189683));
#561=CARTESIAN_POINT('',(25.2963064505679,-3.8055303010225,24.9010925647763));
#562=CARTESIAN_POINT('',(24.9849941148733,-3.77385392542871,25.2619068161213));
#563=CARTESIAN_POINT('',(24.8217699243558,-3.75724568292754,25.4357176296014));
#564=CARTESIAN_POINT('',(24.4813524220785,-3.72260782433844,25.7689123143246));
#565=CARTESIAN_POINT('',(24.3041593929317,-3.70457823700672,25.9282964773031));
#566=CARTESIAN_POINT('',(23.9369192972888,-3.6672111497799,26.2316340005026));
#567=CARTESIAN_POINT('',(23.746862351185,-3.64787264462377,26.3755752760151));
#568=CARTESIAN_POINT('',(23.3553745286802,-3.60803832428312,26.6468659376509));
#569=CARTESIAN_POINT('',(23.1539438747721,-3.58754253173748,26.7742156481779));
#570=CARTESIAN_POINT('',(22.7410978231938,-3.5455349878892,27.0114526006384));
#571=CARTESIAN_POINT('',(22.5296804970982,-3.52402304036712,27.1213364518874));
#572=CARTESIAN_POINT('',(22.0984744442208,-3.48014734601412,27.3228052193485));
#573=CARTESIAN_POINT('',(21.8786886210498,-3.45778389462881,27.4143964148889));
#574=CARTESIAN_POINT('',(21.431905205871,-3.41232318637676,27.5788085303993));
#575=CARTESIAN_POINT('',(21.20489740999,-3.38922489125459,27.6516014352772));
#576=CARTESIAN_POINT('',(20.7455990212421,-3.34249077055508,27.7777299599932));
#577=CARTESIAN_POINT('',(20.5133085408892,-3.31885495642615,27.8310659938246));
#578=CARTESIAN_POINT('',(20.0450990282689,-3.27121411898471,27.9179123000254));
#579=CARTESIAN_POINT('',(19.8091801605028,-3.24720911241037,27.9514234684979));
#580=CARTESIAN_POINT('',(19.3353786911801,-3.19899928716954,27.998395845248));
#581=CARTESIAN_POINT('',(19.0974961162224,-3.17479447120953,28.0118573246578));
#582=CARTESIAN_POINT('',(18.6210318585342,-3.12631370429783,28.0186515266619));
#583=CARTESIAN_POINT('',(18.3824496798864,-3.10203770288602,28.0119491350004));
#584=CARTESIAN_POINT('',(17.9067737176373,-3.05363714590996,27.9784021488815));
#585=CARTESIAN_POINT('',(17.6696794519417,-3.02951254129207,27.9515644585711));
#586=CARTESIAN_POINT('',(17.1984347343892,-2.98156286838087,27.8779318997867));
#587=CARTESIAN_POINT('',(16.9642861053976,-2.95773798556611,27.8311252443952));
#588=CARTESIAN_POINT('',(16.500740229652,-2.91057167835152,27.7178937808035));
#589=CARTESIAN_POINT('',(16.2713428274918,-2.88723023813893,27.6514696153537));
#590=CARTESIAN_POINT('',(15.8183308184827,-2.84113576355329,27.4992830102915));
#591=CARTESIAN_POINT('',(15.5947326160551,-2.81838439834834,27.4134712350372));
#592=CARTESIAN_POINT('',(15.155526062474,-2.77369464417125,27.2232203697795));
#593=CARTESIAN_POINT('',(14.9399175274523,-2.75175623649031,27.1187817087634));
#594=CARTESIAN_POINT('',(14.5185439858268,-2.70888101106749,26.8921972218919));
#595=CARTESIAN_POINT('',(14.3127646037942,-2.68794273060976,26.7700783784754));
#596=CARTESIAN_POINT('',(13.9122402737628,-2.64718893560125,26.5089238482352));
#597=CARTESIAN_POINT('',(13.7174893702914,-2.62737281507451,26.3698974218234));
#598=CARTESIAN_POINT('',(13.4370604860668,-2.59883886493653,26.1513001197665));
#599=CARTESIAN_POINT('',(13.3466503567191,-2.58963953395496,26.077788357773));
#600=CARTESIAN_POINT('',(13.1690334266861,-2.57156681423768,25.9272071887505));
#601=CARTESIAN_POINT('',(13.081822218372,-2.56269297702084,25.8501430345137));
#602=CARTESIAN_POINT('',(12.9962083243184,-2.55398166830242,25.7713054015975));
#603=B_SPLINE_CURVE_WITH_KNOTS('',3,(#517,#518,#519,#520,#521,#522,#523,#524,#525,#526,#527,
#528,#529,#530,#531,#532,#533,#534,#535,#536,#537,#538,#539,#540,#541,#542,#543,#544,#545,#546,
#547,#548,#549,#550,#551,#552,#553,#554,#555,#556,#557,#558,#559,#560,#561,#562,#563,#564,#565,
#566,#567,#568,#569,#570,#571,#572,#573,#574,#575,#576,#577,#578,#579,#580,#581,#582,#583,#584,
#585,#586,#587,#588,#589,#590,#591,#592,#593,#594,#595,#596,#597,#598,#599,#600,#601,#602),
.UNSPECIFIED.,.F.,.F.,(4,2,2,2,2,2,2,2,2,2,2,2,2,2,2,2,2,2,2,2,2,2,2,2,2,2,2,2,2,2,2,2,2,2,2,2,
2,2,2,2,2,2,4),(0.,0.71746500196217,1.4349005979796,2.15186197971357,2.86881327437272,
3.58612197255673,4.30344145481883,5.02060549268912,5.73776568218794,6.45421425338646,
7.17091088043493,7.88758704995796,8.60427405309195,9.32042697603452,10.0365952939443,
10.7525852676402,11.4688230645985,12.1848033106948,12.9007986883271,13.6167929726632,
14.3328024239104,15.0489937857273,15.7651856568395,16.481382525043,17.1975649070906,
17.9143037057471,18.6310284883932,19.3478922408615,20.0645094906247,20.7821886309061,
21.4998524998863,22.2174839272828,22.9351056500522,23.6539777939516,24.3726035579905,
25.0916540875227,25.8106810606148,26.5315587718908,27.2524198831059,27.9721922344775,
28.691572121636,29.0421492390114,29.3922236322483),.UNSPECIFIED.);
#604=EDGE_CURVE('E366',#443,#512,#603,.T.);
#605=ORIENTED_EDGE('',*,*,#604,.F.);
#606=ORIENTED_EDGE('',*,*,#444,.T.);
#607=CARTESIAN_POINT('',(22.269940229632,3.49919143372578,11.7897956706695));
#608=CARTESIAN_POINT('',(22.4863520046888,3.52114156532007,11.8893700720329));
#609=CARTESIAN_POINT('',(22.6985645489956,3.54266577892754,11.9981550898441));
#610=CARTESIAN_POINT('',(23.1131258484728,3.58471374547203,12.2332767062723));
#611=CARTESIAN_POINT('',(23.3154750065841,3.60523753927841,12.3596125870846));
#612=CARTESIAN_POINT('',(23.7087322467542,3.64512468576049,12.6288856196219));
#613=CARTESIAN_POINT('',(23.8996477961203,3.66448879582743,12.7718117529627));
#614=CARTESIAN_POINT('',(24.2688239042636,3.7019334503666,13.0733134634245));
#615=CARTESIAN_POINT('',(24.4470846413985,3.72001401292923,13.2318888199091));
#616=CARTESIAN_POINT('',(24.7897674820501,3.75477151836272,13.5636531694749));
#617=CARTESIAN_POINT('',(24.9541826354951,3.77144775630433,13.7368494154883));
#618=CARTESIAN_POINT('',(25.267902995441,3.80326766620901,14.0965604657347));
#619=CARTESIAN_POINT('',(25.417207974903,3.81841131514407,14.2830754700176));
#620=CARTESIAN_POINT('',(25.6996071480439,3.84705439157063,14.6680547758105));
#621=CARTESIAN_POINT('',(25.8327048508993,3.86055417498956,14.8665164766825));
#622=CARTESIAN_POINT('',(26.081774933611,3.88581676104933,15.2740136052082));
#623=CARTESIAN_POINT('',(26.1977474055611,3.89757957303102,15.4830489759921));
#624=CARTESIAN_POINT('',(26.4116306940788,3.91927324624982,15.9099919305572));
#625=CARTESIAN_POINT('',(26.5095595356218,3.92920593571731,16.1278903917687));
#626=CARTESIAN_POINT('',(26.6868305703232,3.94718611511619,16.571284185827));
#627=CARTESIAN_POINT('',(26.7661663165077,3.95523295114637,16.7967821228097));
#628=CARTESIAN_POINT('',(26.9056383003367,3.96937926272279,17.2536918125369));
#629=CARTESIAN_POINT('',(26.9657750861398,3.97547879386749,17.4851033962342));
#630=CARTESIAN_POINT('',(27.0664230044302,3.98568727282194,17.9522026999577));
#631=CARTESIAN_POINT('',(27.1069338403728,3.98979619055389,18.1878904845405));
#632=CARTESIAN_POINT('',(27.1680156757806,3.99599157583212,18.6616810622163));
#633=CARTESIAN_POINT('',(27.1886017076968,3.99807956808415,18.8997818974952));
#634=CARTESIAN_POINT('',(27.2097403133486,4.00022360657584,19.3768855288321));
#635=CARTESIAN_POINT('',(27.2102924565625,4.00027960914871,19.6158883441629));
#636=CARTESIAN_POINT('',(27.1913606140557,3.99835939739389,20.0930311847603));
#637=CARTESIAN_POINT('',(27.1718816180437,3.99638368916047,20.3311714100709));
#638=CARTESIAN_POINT('',(27.1130239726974,3.9904138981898,20.8050381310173));
#639=CARTESIAN_POINT('',(27.0736384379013,3.98641911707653,21.0407637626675));
#640=CARTESIAN_POINT('',(26.9752633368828,3.97644116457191,21.5079559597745));
#641=CARTESIAN_POINT('',(26.9162808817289,3.97045871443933,21.7394240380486));
#642=CARTESIAN_POINT('',(26.7791278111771,3.95654760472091,22.1965491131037));
#643=CARTESIAN_POINT('',(26.7009567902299,3.94861890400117,22.4222059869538));
#644=CARTESIAN_POINT('',(26.5259851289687,3.93087194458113,22.8661004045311));
#645=CARTESIAN_POINT('',(26.4291845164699,3.92105368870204,23.0843379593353));
#646=CARTESIAN_POINT('',(26.217641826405,3.89959741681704,23.5118494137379));
#647=CARTESIAN_POINT('',(26.1028993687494,3.88795936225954,23.7211231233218));
#648=CARTESIAN_POINT('',(25.8562607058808,3.86294338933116,24.1292701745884));
#649=CARTESIAN_POINT('',(25.7243600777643,3.84956502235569,24.3281408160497));
#650=CARTESIAN_POINT('',(25.4443684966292,3.82116614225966,24.7140134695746));
#651=CARTESIAN_POINT('',(25.2962775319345,3.80614562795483,24.9010154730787));
#652=CARTESIAN_POINT('',(24.9849596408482,3.77456939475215,25.26182725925));
#653=CARTESIAN_POINT('',(24.821732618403,3.75801366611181,25.4356369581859));
#654=CARTESIAN_POINT('',(24.4813092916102,3.72348533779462,25.768829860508));
#655=CARTESIAN_POINT('',(24.3041132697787,3.70551276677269,25.9282133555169));
#656=CARTESIAN_POINT('',(23.9368653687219,3.66826368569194,26.2315514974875));
#657=CARTESIAN_POINT('',(23.7468034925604,3.64898616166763,26.3754939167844));
#658=CARTESIAN_POINT('',(23.3553055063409,3.60927745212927,26.6467872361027));
#659=CARTESIAN_POINT('',(23.1538696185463,3.58884628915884,26.7741384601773));
#660=CARTESIAN_POINT('',(22.7410119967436,3.54697112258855,27.0113794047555));
#661=CARTESIAN_POINT('',(22.5295882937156,3.52552691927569,27.1212656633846));
#662=CARTESIAN_POINT('',(22.0983691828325,3.48178939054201,27.3227397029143));
#663=CARTESIAN_POINT('',(21.8785766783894,3.45949635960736,27.414333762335));
#664=CARTESIAN_POINT('',(21.4317737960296,3.41417820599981,27.5787543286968));
#665=CARTESIAN_POINT('',(21.2047530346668,3.3911520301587,27.6515523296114));
#666=CARTESIAN_POINT('',(20.7454281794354,3.34456380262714,27.7776907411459));
#667=CARTESIAN_POINT('',(20.5131241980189,3.32100176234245,27.8310315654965));
#668=CARTESIAN_POINT('',(20.0448917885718,3.273510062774,27.9178864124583));
#669=CARTESIAN_POINT('',(19.808963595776,3.24958042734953,27.9514017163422));
#670=CARTESIAN_POINT('',(19.33514312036,3.20152194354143,27.9983830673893));
#671=CARTESIAN_POINT('',(19.09725086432,3.17739309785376,28.0118493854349));
#672=CARTESIAN_POINT('',(18.6207682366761,3.1290645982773,28.0186540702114));
#673=CARTESIAN_POINT('',(18.3821773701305,3.10486489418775,28.0119574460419));
#674=CARTESIAN_POINT('',(17.906483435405,3.05661638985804,27.9784231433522));
#675=CARTESIAN_POINT('',(17.6693798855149,3.03256754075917,27.951592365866));
#676=CARTESIAN_POINT('',(17.1980962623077,2.98476636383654,27.8779717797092));
#677=CARTESIAN_POINT('',(16.9639182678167,2.96101424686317,27.831168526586));
#678=CARTESIAN_POINT('',(16.5003145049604,2.91399201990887,27.7179420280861));
#679=CARTESIAN_POINT('',(16.2708885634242,2.89072189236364,27.6515194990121));
#680=CARTESIAN_POINT('',(15.8177881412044,2.84476499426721,27.4993238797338));
#681=CARTESIAN_POINT('',(15.594130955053,2.8220799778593,27.4134987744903));
#682=CARTESIAN_POINT('',(15.1548092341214,2.77752062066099,27.2232142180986));
#683=CARTESIAN_POINT('',(14.9391444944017,2.75564625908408,27.118755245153));
#684=CARTESIAN_POINT('',(14.5177209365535,2.71290226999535,26.892155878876));
#685=CARTESIAN_POINT('',(14.3119451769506,2.69203092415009,26.7700472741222));
#686=CARTESIAN_POINT('',(13.9114301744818,2.6514076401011,26.508917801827));
#687=CARTESIAN_POINT('',(13.7166843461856,2.63165503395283,26.3699071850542));
#688=CARTESIAN_POINT('',(13.4640710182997,2.60603306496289,26.1730131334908));
#689=CARTESIAN_POINT('',(13.4007037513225,2.59960587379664,26.1221461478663));
#690=CARTESIAN_POINT('',(13.2755127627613,2.58690804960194,26.0186683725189));
#691=CARTESIAN_POINT('',(13.2136874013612,2.58063725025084,25.9660595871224));
#692=CARTESIAN_POINT('',(13.1526156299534,2.57444288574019,25.9125680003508));
#693=B_SPLINE_CURVE_WITH_KNOTS('',3,(#607,#608,#609,#610,#611,#612,#613,#614,#615,#616,#617,
#618,#619,#620,#621,#622,#623,#624,#625,#626,#627,#628,#629,#630,#631,#632,#633,#634,#635,#636,
#637,#638,#639,#640,#641,#642,#643,#644,#645,#646,#647,#648,#649,#650,#651,#652,#653,#654,#655,
#656,#657,#658,#659,#660,#661,#662,#663,#664,#665,#666,#667,#668,#669,#670,#671,#672,#673,#674,
#675,#676,#677,#678,#679,#680,#681,#682,#683,#684,#685,#686,#687,#688,#689,#690,#691,#692),
.UNSPECIFIED.,.F.,.F.,(4,2,2,2,2,2,2,2,2,2,2,2,2,2,2,2,2,2,2,2,2,2,2,2,2,2,2,2,2,2,2,2,2,2,2,2,
2,2,2,2,2,2,4),(0.,0.717472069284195,1.43491480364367,2.15188374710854,2.8688425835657,
3.58615919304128,4.30348657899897,5.02065837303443,5.73782631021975,6.4542738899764,
7.17096952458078,7.88764469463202,8.60433069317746,9.3204755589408,10.0366358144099,
10.7526177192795,11.468847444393,12.1848175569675,12.9008028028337,13.6167869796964,
14.3327863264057,15.0489706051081,15.7651554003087,16.4813447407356,17.197519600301,
17.914257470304,18.6309813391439,19.3478470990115,20.0644663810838,20.7821661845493,
21.4998507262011,22.2174888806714,22.9351173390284,23.6539918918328,24.3726201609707,
25.0917329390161,25.8108194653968,26.5318570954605,27.2528762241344,27.9726125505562,
28.6919145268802,28.936425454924,29.1806641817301),.UNSPECIFIED.);
#694=EDGE_CURVE('E534',#434,#514,#693,.T.);
#695=ORIENTED_EDGE('',*,*,#694,.T.);
#696=EDGE_LOOP('',(#516,#605,#606,#695));
#697=FACE_BOUND('',#696,.T.);
#698=ADVANCED_FACE('F300',(#697),#505,.T.);
#699=CARTESIAN_POINT('',(-16.3437132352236,2.89810832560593,27.6698599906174));
#700=VERTEX_POINT('',#699);
#701=CARTESIAN_POINT('',(-16.3443249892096,-2.89465625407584,27.6698599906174));
#702=VERTEX_POINT('',#701);
#703=EDGE_CURVE('E403',#700,#702,#510,.T.);
#704=ORIENTED_EDGE('',*,*,#703,.F.);
#705=CARTESIAN_POINT('',(-22.269940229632,3.49919143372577,11.7897956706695));
#706=CARTESIAN_POINT('',(-22.4863520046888,3.52114156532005,11.8893700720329));
#707=CARTESIAN_POINT('',(-22.6985645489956,3.54266577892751,11.9981550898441));
#708=CARTESIAN_POINT('',(-23.1131258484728,3.584713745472,12.2332767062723));
#709=CARTESIAN_POINT('',(-23.3154750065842,3.60523753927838,12.3596125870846));
#710=CARTESIAN_POINT('',(-23.7087322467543,3.64512468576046,12.628885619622));
#711=CARTESIAN_POINT('',(-23.8996477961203,3.6644887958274,12.7718117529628));
#712=CARTESIAN_POINT('',(-24.2688239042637,3.70193345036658,13.0733134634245));
#713=CARTESIAN_POINT('',(-24.4470846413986,3.72001401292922,13.2318888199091));
#714=CARTESIAN_POINT('',(-24.7897674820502,3.7547715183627,13.5636531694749));
#715=CARTESIAN_POINT('',(-24.9541826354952,3.7714477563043,13.7368494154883));
#716=CARTESIAN_POINT('',(-25.267902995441,3.80326766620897,14.0965604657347));
#717=CARTESIAN_POINT('',(-25.4172079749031,3.81841131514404,14.2830754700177));
#718=CARTESIAN_POINT('',(-25.6996071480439,3.8470543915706,14.6680547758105));
#719=CARTESIAN_POINT('',(-25.8327048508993,3.86055417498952,14.8665164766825));
#720=CARTESIAN_POINT('',(-26.081774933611,3.8858167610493,15.2740136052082));
#721=CARTESIAN_POINT('',(-26.1977474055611,3.89757957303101,15.4830489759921));
#722=CARTESIAN_POINT('',(-26.4116306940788,3.9192732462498,15.9099919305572));
#723=CARTESIAN_POINT('',(-26.5095595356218,3.92920593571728,16.1278903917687));
#724=CARTESIAN_POINT('',(-26.6868305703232,3.94718611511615,16.571284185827));
#725=CARTESIAN_POINT('',(-26.7661663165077,3.95523295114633,16.7967821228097));
#726=CARTESIAN_POINT('',(-26.9056383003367,3.96937926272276,17.2536918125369));
#727=CARTESIAN_POINT('',(-26.9657750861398,3.97547879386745,17.4851033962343));
#728=CARTESIAN_POINT('',(-27.0664230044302,3.98568727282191,17.9522026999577));
#729=CARTESIAN_POINT('',(-27.1069338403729,3.98979619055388,18.1878904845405));
#730=CARTESIAN_POINT('',(-27.1680156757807,3.99599157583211,18.6616810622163));
#731=CARTESIAN_POINT('',(-27.1886017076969,3.99807956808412,18.8997818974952));
#732=CARTESIAN_POINT('',(-27.2097403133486,4.0002236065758,19.3768855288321));
#733=CARTESIAN_POINT('',(-27.2102924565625,4.00027960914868,19.6158883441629));
#734=CARTESIAN_POINT('',(-27.1913606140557,3.99835939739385,20.0930311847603));
#735=CARTESIAN_POINT('',(-27.1718816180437,3.99638368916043,20.331171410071));
#736=CARTESIAN_POINT('',(-27.1130239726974,3.99041389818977,20.8050381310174));
#737=CARTESIAN_POINT('',(-27.0736384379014,3.98641911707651,21.0407637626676));
#738=CARTESIAN_POINT('',(-26.9752633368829,3.97644116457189,21.5079559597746));
#739=CARTESIAN_POINT('',(-26.9162808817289,3.97045871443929,21.7394240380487));
#740=CARTESIAN_POINT('',(-26.779127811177,3.95654760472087,22.1965491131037));
#741=CARTESIAN_POINT('',(-26.7009567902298,3.94861890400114,22.4222059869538));
#742=CARTESIAN_POINT('',(-26.5259851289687,3.93087194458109,22.8661004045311));
#743=CARTESIAN_POINT('',(-26.4291845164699,3.921053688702,23.0843379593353));
#744=CARTESIAN_POINT('',(-26.217641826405,3.89959741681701,23.5118494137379));
#745=CARTESIAN_POINT('',(-26.1028993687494,3.88795936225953,23.7211231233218));
#746=CARTESIAN_POINT('',(-25.8562607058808,3.86294338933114,24.1292701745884));
#747=CARTESIAN_POINT('',(-25.7243600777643,3.84956502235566,24.3281408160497));
#748=CARTESIAN_POINT('',(-25.4443684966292,3.82116614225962,24.7140134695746));
#749=CARTESIAN_POINT('',(-25.2962775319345,3.80614562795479,24.9010154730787));
#750=CARTESIAN_POINT('',(-24.9849596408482,3.77456939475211,25.26182725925));
#751=CARTESIAN_POINT('',(-24.8217326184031,3.75801366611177,25.4356369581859));
#752=CARTESIAN_POINT('',(-24.4813092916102,3.72348533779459,25.768829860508));
#753=CARTESIAN_POINT('',(-24.3041132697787,3.70551276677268,25.9282133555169));
#754=CARTESIAN_POINT('',(-23.9368653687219,3.66826368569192,26.2315514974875));
#755=CARTESIAN_POINT('',(-23.7468034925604,3.6489861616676,26.3754939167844));
#756=CARTESIAN_POINT('',(-23.355305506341,3.60927745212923,26.6467872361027));
#757=CARTESIAN_POINT('',(-23.1538696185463,3.58884628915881,26.7741384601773));
#758=CARTESIAN_POINT('',(-22.7410119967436,3.54697112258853,27.0113794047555));
#759=CARTESIAN_POINT('',(-22.5295882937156,3.52552691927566,27.1212656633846));
#760=CARTESIAN_POINT('',(-22.0983691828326,3.48178939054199,27.3227397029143));
#761=CARTESIAN_POINT('',(-21.8785766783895,3.45949635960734,27.414333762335));
#762=CARTESIAN_POINT('',(-21.4317737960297,3.4141782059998,27.5787543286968));
#763=CARTESIAN_POINT('',(-21.2047530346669,3.39115203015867,27.6515523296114));
#764=CARTESIAN_POINT('',(-20.7454281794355,3.34456380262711,27.7776907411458));
#765=CARTESIAN_POINT('',(-20.513124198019,3.32100176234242,27.8310315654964));
#766=CARTESIAN_POINT('',(-20.0448917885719,3.27351006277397,27.9178864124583));
#767=CARTESIAN_POINT('',(-19.808963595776,3.2495804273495,27.9514017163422));
#768=CARTESIAN_POINT('',(-19.33514312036,3.20152194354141,27.9983830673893));
#769=CARTESIAN_POINT('',(-19.09725086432,3.17739309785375,28.0118493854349));
#770=CARTESIAN_POINT('',(-18.6207682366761,3.12906459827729,28.0186540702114));
#771=CARTESIAN_POINT('',(-18.3821773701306,3.10486489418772,28.0119574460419));
#772=CARTESIAN_POINT('',(-17.906483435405,3.056616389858,27.9784231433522));
#773=CARTESIAN_POINT('',(-17.669379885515,3.03256754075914,27.951592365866));
#774=CARTESIAN_POINT('',(-17.1980962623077,2.9847663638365,27.8779717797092));
#775=CARTESIAN_POINT('',(-16.9639182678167,2.96101424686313,27.831168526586));
#776=CARTESIAN_POINT('',(-16.5003145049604,2.91399201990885,27.7179420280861));
#777=CARTESIAN_POINT('',(-16.2708885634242,2.89072189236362,27.6515194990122));
#778=CARTESIAN_POINT('',(-15.8177881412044,2.8447649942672,27.4993238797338));
#779=CARTESIAN_POINT('',(-15.594130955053,2.82207997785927,27.4134987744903));
#780=CARTESIAN_POINT('',(-15.1548092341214,2.77752062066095,27.2232142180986));
#781=CARTESIAN_POINT('',(-14.9391444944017,2.75564625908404,27.118755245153));
#782=CARTESIAN_POINT('',(-14.5177209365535,2.71290226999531,26.892155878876));
#783=CARTESIAN_POINT('',(-14.3119451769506,2.69203092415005,26.7700472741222));
#784=CARTESIAN_POINT('',(-13.9114301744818,2.65140764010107,26.508917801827));
#785=CARTESIAN_POINT('',(-13.7166843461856,2.63165503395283,26.3699071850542));
#786=CARTESIAN_POINT('',(-13.4640710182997,2.60603306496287,26.1730131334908));
#787=CARTESIAN_POINT('',(-13.4007037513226,2.59960587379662,26.1221461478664));
#788=CARTESIAN_POINT('',(-13.2755127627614,2.58690804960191,26.0186683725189));
#789=CARTESIAN_POINT('',(-13.2136874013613,2.58063725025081,25.9660595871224));
#790=CARTESIAN_POINT('',(-13.1526156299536,2.57444288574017,25.9125680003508));
#791=B_SPLINE_CURVE_WITH_KNOTS('',3,(#705,#706,#707,#708,#709,#710,#711,#712,#713,#714,#715,
#716,#717,#718,#719,#720,#721,#722,#723,#724,#725,#726,#727,#728,#729,#730,#731,#732,#733,#734,
#735,#736,#737,#738,#739,#740,#741,#742,#743,#744,#745,#746,#747,#748,#749,#750,#751,#752,#753,
#754,#755,#756,#757,#758,#759,#760,#761,#762,#763,#764,#765,#766,#767,#768,#769,#770,#771,#772,
#773,#774,#775,#776,#777,#778,#779,#780,#781,#782,#783,#784,#785,#786,#787,#788,#789,#790),
.UNSPECIFIED.,.F.,.F.,(4,2,2,2,2,2,2,2,2,2,2,2,2,2,2,2,2,2,2,2,2,2,2,2,2,2,2,2,2,2,2,2,2,2,2,2,
2,2,2,2,2,2,4),(0.,0.717472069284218,1.43491480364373,2.1518837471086,2.86884258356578,
3.58615919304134,4.30348657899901,5.02065837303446,5.73782631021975,6.45427388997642,
7.1709695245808,7.88764469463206,8.60433069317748,9.32047555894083,10.0366358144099,
10.7526177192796,11.4688474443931,12.1848175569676,12.9008028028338,13.6167869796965,
14.3327863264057,15.0489706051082,15.7651554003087,16.4813447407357,17.197519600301,
17.914257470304,18.6309813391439,19.3478470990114,20.0644663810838,20.7821661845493,
21.4998507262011,22.2174888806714,22.9351173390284,23.6539918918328,24.3726201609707,
25.0917329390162,25.8108194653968,26.5318570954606,27.2528762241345,27.9726125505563,
28.6919145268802,28.9364254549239,29.18066418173),.UNSPECIFIED.);
#792=CARTESIAN_POINT('',(-22.2703747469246,3.49923550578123,11.7899956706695));
#793=VERTEX_POINT('',#792);
#794=EDGE_CURVE('E460',#793,#700,#791,.T.);
#795=ORIENTED_EDGE('',*,*,#794,.F.);
#796=CARTESIAN_POINT('',(-22.2706216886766,-3.49766351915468,11.7899956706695));
#797=VERTEX_POINT('',#796);
#798=EDGE_CURVE('E406',#793,#797,#441,.T.);
#799=ORIENTED_EDGE('',*,*,#798,.T.);
#800=CARTESIAN_POINT('',(-22.2701871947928,-3.49761930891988,11.7897956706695));
#801=CARTESIAN_POINT('',(-22.4865890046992,-3.51963843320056,11.8893708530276));
#802=CARTESIAN_POINT('',(-22.6987916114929,-3.54123028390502,11.9981566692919));
#803=CARTESIAN_POINT('',(-23.1133331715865,-3.5834103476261,12.2332797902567));
#804=CARTESIAN_POINT('',(-23.3156725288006,-3.60399860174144,12.359616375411));
#805=CARTESIAN_POINT('',(-23.7089103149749,-3.64401098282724,12.6288905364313));
#806=CARTESIAN_POINT('',(-23.8998162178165,-3.66343587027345,12.7718170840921));
#807=CARTESIAN_POINT('',(-24.268973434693,-3.70099802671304,13.0733193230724));
#808=CARTESIAN_POINT('',(-24.4472249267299,-3.71913531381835,13.2318947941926));
#809=CARTESIAN_POINT('',(-24.7898897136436,-3.75400183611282,13.5636589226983));
#810=CARTESIAN_POINT('',(-24.9542960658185,-3.77073036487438,13.7368548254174));
#811=CARTESIAN_POINT('',(-25.2679995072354,-3.80265003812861,14.0965647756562));
#812=CARTESIAN_POINT('',(-25.4172963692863,-3.81784115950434,14.2830790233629));
#813=CARTESIAN_POINT('',(-25.6996801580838,-3.84657402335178,14.6680564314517));
#814=CARTESIAN_POINT('',(-25.8327705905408,-3.86011612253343,14.8665169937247));
#815=CARTESIAN_POINT('',(-26.0818270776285,-3.88545789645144,15.2740114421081));
#816=CARTESIAN_POINT('',(-26.1977932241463,-3.89725758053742,15.4830452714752));
#817=CARTESIAN_POINT('',(-26.4116662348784,-3.91901939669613,15.9099873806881));
#818=CARTESIAN_POINT('',(-26.5095909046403,-3.92898334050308,16.1278866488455));
#819=CARTESIAN_POINT('',(-26.6868542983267,-3.94702008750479,16.5712819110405));
#820=CARTESIAN_POINT('',(-26.7661865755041,-3.95509223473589,16.7967805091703));
#821=CARTESIAN_POINT('',(-26.9056523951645,-3.96928303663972,17.2536913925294));
#822=CARTESIAN_POINT('',(-26.9657864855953,-3.97540174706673,17.4851035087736));
#823=CARTESIAN_POINT('',(-27.0664298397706,-3.98564232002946,17.9522037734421));
#824=CARTESIAN_POINT('',(-27.1069388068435,-3.98976415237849,18.187891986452));
#825=CARTESIAN_POINT('',(-27.1680180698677,-3.99597903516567,18.6616856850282));
#826=CARTESIAN_POINT('',(-27.1886032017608,-3.99807359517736,18.8997892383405));
#827=CARTESIAN_POINT('',(-27.2097404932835,-4.00022433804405,19.3768982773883));
#828=CARTESIAN_POINT('',(-27.2102922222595,-4.00028047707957,19.6159037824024));
#829=CARTESIAN_POINT('',(-27.1913600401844,-3.99835410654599,20.0930519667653));
#830=CARTESIAN_POINT('',(-27.1718811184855,-3.99637210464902,20.331194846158));
#831=CARTESIAN_POINT('',(-27.1130241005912,-3.99038333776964,20.8050668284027));
#832=CARTESIAN_POINT('',(-27.0736391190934,-3.98637587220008,21.0407950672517));
#833=CARTESIAN_POINT('',(-26.9752654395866,-3.97636624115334,21.5079930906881));
#834=CARTESIAN_POINT('',(-26.9162837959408,-3.97036479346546,21.739464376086));
#835=CARTESIAN_POINT('',(-26.7791326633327,-3.95640951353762,22.1965957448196));
#836=CARTESIAN_POINT('',(-26.7009627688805,-3.94845564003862,22.4222557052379));
#837=CARTESIAN_POINT('',(-26.5259936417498,-3.93065233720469,22.8661561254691));
#838=CARTESIAN_POINT('',(-26.4291944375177,-3.92080291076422,23.0843965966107));
#839=CARTESIAN_POINT('',(-26.2176548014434,-3.89927851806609,23.5119136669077));
#840=CARTESIAN_POINT('',(-26.1029139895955,-3.88760351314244,23.7211900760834));
#841=CARTESIAN_POINT('',(-25.8562793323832,-3.86250816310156,24.129341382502));
#842=CARTESIAN_POINT('',(-25.7243811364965,-3.84908737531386,24.328213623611));
#843=CARTESIAN_POINT('',(-25.4443947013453,-3.82059844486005,24.7140892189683));
#844=CARTESIAN_POINT('',(-25.2963064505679,-3.80553030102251,24.9010925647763));
#845=CARTESIAN_POINT('',(-24.9849941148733,-3.77385392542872,25.2619068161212));
#846=CARTESIAN_POINT('',(-24.8217699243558,-3.75724568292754,25.4357176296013));
#847=CARTESIAN_POINT('',(-24.4813524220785,-3.72260782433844,25.7689123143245));
#848=CARTESIAN_POINT('',(-24.3041593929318,-3.70457823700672,25.9282964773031));
#849=CARTESIAN_POINT('',(-23.9369192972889,-3.66721114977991,26.2316340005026));
#850=CARTESIAN_POINT('',(-23.746862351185,-3.64787264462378,26.375575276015));
#851=CARTESIAN_POINT('',(-23.3553745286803,-3.60803832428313,26.6468659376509));
#852=CARTESIAN_POINT('',(-23.1539438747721,-3.58754253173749,26.7742156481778));
#853=CARTESIAN_POINT('',(-22.7410978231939,-3.54553498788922,27.0114526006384));
#854=CARTESIAN_POINT('',(-22.5296804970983,-3.52402304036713,27.1213364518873));
#855=CARTESIAN_POINT('',(-22.0984744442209,-3.48014734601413,27.3228052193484));
#856=CARTESIAN_POINT('',(-21.8786886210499,-3.45778389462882,27.4143964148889));
#857=CARTESIAN_POINT('',(-21.4319052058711,-3.41232318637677,27.5788085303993));
#858=CARTESIAN_POINT('',(-21.2048974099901,-3.38922489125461,27.6516014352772));
#859=CARTESIAN_POINT('',(-20.7455990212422,-3.34249077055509,27.7777299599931));
#860=CARTESIAN_POINT('',(-20.5133085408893,-3.31885495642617,27.8310659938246));
#861=CARTESIAN_POINT('',(-20.045099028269,-3.27121411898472,27.9179123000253));
#862=CARTESIAN_POINT('',(-19.8091801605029,-3.24720911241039,27.9514234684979));
#863=CARTESIAN_POINT('',(-19.3353786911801,-3.19899928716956,27.998395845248));
#864=CARTESIAN_POINT('',(-19.0974961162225,-3.17479447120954,28.0118573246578));
#865=CARTESIAN_POINT('',(-18.6210318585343,-3.12631370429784,28.0186515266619));
#866=CARTESIAN_POINT('',(-18.3824496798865,-3.10203770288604,28.0119491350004));
#867=CARTESIAN_POINT('',(-17.9067737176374,-3.05363714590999,27.9784021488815));
#868=CARTESIAN_POINT('',(-17.6696794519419,-3.02951254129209,27.9515644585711));
#869=CARTESIAN_POINT('',(-17.1984347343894,-2.98156286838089,27.8779318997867));
#870=CARTESIAN_POINT('',(-16.9642861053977,-2.95773798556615,27.8311252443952));
#871=CARTESIAN_POINT('',(-16.5007402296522,-2.91057167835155,27.7178937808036));
#872=CARTESIAN_POINT('',(-16.271342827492,-2.88723023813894,27.6514696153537));
#873=CARTESIAN_POINT('',(-15.8183308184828,-2.8411357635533,27.4992830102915));
#874=CARTESIAN_POINT('',(-15.5947326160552,-2.81838439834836,27.4134712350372));
#875=CARTESIAN_POINT('',(-15.1555260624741,-2.77369464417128,27.2232203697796));
#876=CARTESIAN_POINT('',(-14.9399175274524,-2.75175623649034,27.1187817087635));
#877=CARTESIAN_POINT('',(-14.5185439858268,-2.70888101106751,26.8921972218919));
#878=CARTESIAN_POINT('',(-14.3127646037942,-2.68794273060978,26.7700783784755));
#879=CARTESIAN_POINT('',(-13.9122402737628,-2.64718893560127,26.5089238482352));
#880=CARTESIAN_POINT('',(-13.7174893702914,-2.62737281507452,26.3698974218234));
#881=CARTESIAN_POINT('',(-13.4370604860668,-2.59883886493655,26.1513001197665));
#882=CARTESIAN_POINT('',(-13.3466503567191,-2.58963953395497,26.077788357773));
#883=CARTESIAN_POINT('',(-13.1690334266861,-2.57156681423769,25.9272071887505));
#884=CARTESIAN_POINT('',(-13.081822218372,-2.56269297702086,25.8501430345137));
#885=CARTESIAN_POINT('',(-12.9962083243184,-2.55398166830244,25.7713054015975));
#886=B_SPLINE_CURVE_WITH_KNOTS('',3,(#800,#801,#802,#803,#804,#805,#806,#807,#808,#809,#810,
#811,#812,#813,#814,#815,#816,#817,#818,#819,#820,#821,#822,#823,#824,#825,#826,#827,#828,#829,
#830,#831,#832,#833,#834,#835,#836,#837,#838,#839,#840,#841,#842,#843,#844,#845,#846,#847,#848,
#849,#850,#851,#852,#853,#854,#855,#856,#857,#858,#859,#860,#861,#862,#863,#864,#865,#866,#867,
#868,#869,#870,#871,#872,#873,#874,#875,#876,#877,#878,#879,#880,#881,#882,#883,#884,#885),
.UNSPECIFIED.,.F.,.F.,(4,2,2,2,2,2,2,2,2,2,2,2,2,2,2,2,2,2,2,2,2,2,2,2,2,2,2,2,2,2,2,2,2,2,2,2,
2,2,2,2,2,2,4),(0.,0.717465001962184,1.43490059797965,2.15186197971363,2.8688132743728,
3.58612197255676,4.30344145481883,5.02060549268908,5.73776568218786,6.45421425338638,
7.17091088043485,7.88758704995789,8.60427405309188,9.32042697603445,10.0365952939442,
10.7525852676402,11.4688230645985,12.1848033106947,12.9007986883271,13.6167929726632,
14.3328024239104,15.0489937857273,15.7651856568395,16.481382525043,17.1975649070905,
17.9143037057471,18.6310284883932,19.3478922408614,20.0645094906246,20.782188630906,
21.4998524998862,22.2174839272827,22.9351056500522,23.6539777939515,24.3726035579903,
25.0916540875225,25.8106810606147,26.5315587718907,27.2524198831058,27.9721922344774,
28.691572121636,29.0421492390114,29.3922236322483),.UNSPECIFIED.);
#887=EDGE_CURVE('E474',#797,#702,#886,.T.);
#888=ORIENTED_EDGE('',*,*,#887,.T.);
#889=EDGE_LOOP('',(#704,#795,#799,#888));
#890=FACE_BOUND('',#889,.T.);
#891=ADVANCED_FACE('F296',(#890),#505,.T.);
#892=CARTESIAN_POINT('',(0.,0.,84.9379614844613));
#893=DIRECTION('',(0.,0.,1.));
#894=DIRECTION('',(0.,-1.,0.));
#895=AXIS2_PLACEMENT_3D('',#892,#893,#894);
#896=DEGENERATE_TOROIDAL_SURFACE('',#895,0.267106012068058,59.7,.F.);
#897=CARTESIAN_POINT('',(0.,0.,25.5613648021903));
#898=DIRECTION('',(0.,0.,1.));
#899=DIRECTION('',(0.,-1.,0.));
#900=AXIS2_PLACEMENT_3D('',#897,#898,#899);
#901=CIRCLE('',#900,5.93851776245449);
#902=CARTESIAN_POINT('',(0.,-5.93851776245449,25.5613648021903));
#903=VERTEX_POINT('',#902);
#904=EDGE_CURVE('E400',#903,#903,#901,.T.);
#905=ORIENTED_EDGE('',*,*,#904,.F.);
#906=EDGE_LOOP('',(#905));
#907=FACE_BOUND('',#906,.T.);
#908=CARTESIAN_POINT('',(12.9966083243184,-2.55402529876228,26.7872259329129));
#909=CARTESIAN_POINT('',(12.7754529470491,-2.52825709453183,26.7356435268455));
#910=CARTESIAN_POINT('',(12.5528725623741,-2.5117272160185,26.6855038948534));
#911=CARTESIAN_POINT('',(12.1063783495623,-2.49733345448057,26.5884436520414));
#912=CARTESIAN_POINT('',(11.8824643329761,-2.49947227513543,26.5415235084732));
#913=CARTESIAN_POINT('',(11.4348095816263,-2.52261669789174,26.4512357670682));
#914=CARTESIAN_POINT('',(11.2110689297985,-2.54362860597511,26.4078693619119));
#915=CARTESIAN_POINT('',(10.7654590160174,-2.60455176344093,26.3250334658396));
#916=CARTESIAN_POINT('',(10.5435896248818,-2.64446169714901,26.2855637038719));
#917=CARTESIAN_POINT('',(10.1029278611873,-2.74316372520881,26.2107549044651));
#918=CARTESIAN_POINT('',(9.88414203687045,-2.80199107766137,26.1754237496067));
#919=CARTESIAN_POINT('',(9.45174044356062,-2.93823754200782,26.1092665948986));
#920=CARTESIAN_POINT('',(9.23812452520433,-3.01565611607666,26.0784404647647));
#921=CARTESIAN_POINT('',(8.81794496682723,-3.18856082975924,26.0215849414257));
#922=CARTESIAN_POINT('',(8.61137399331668,-3.28402745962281,25.9955504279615));
#923=CARTESIAN_POINT('',(8.20669244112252,-3.49247951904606,25.948470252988));
#924=CARTESIAN_POINT('',(8.00858079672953,-3.60546273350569,25.9274239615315));
#925=CARTESIAN_POINT('',(7.65039872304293,-3.83057518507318,25.8931881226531));
#926=CARTESIAN_POINT('',(7.48897596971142,-3.94045548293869,25.8793019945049));
#927=CARTESIAN_POINT('',(7.17442939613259,-4.17187167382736,25.8554138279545));
#928=CARTESIAN_POINT('',(7.02130457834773,-4.29340616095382,25.8454113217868));
#929=CARTESIAN_POINT('',(6.72399395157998,-4.54769946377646,25.8293490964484));
#930=CARTESIAN_POINT('',(6.57982418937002,-4.68047747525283,25.8232962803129));
#931=CARTESIAN_POINT('',(6.30152732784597,-4.95633540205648,25.8151989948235));
#932=CARTESIAN_POINT('',(6.16740216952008,-5.09941729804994,25.8131552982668));
#933=CARTESIAN_POINT('',(6.03873367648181,-5.2472556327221,25.8131362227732));
#934=B_SPLINE_CURVE_WITH_KNOTS('',3,(#908,#909,#910,#911,#912,#913,#914,#915,#916,#917,#918,
#919,#920,#921,#922,#923,#924,#925,#926,#927,#928,#929,#930,#931,#932,#933),.UNSPECIFIED.,.F.,
.F.,(4,2,2,2,2,2,2,2,2,2,2,2,4),(0.,0.685469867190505,1.37103900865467,2.05683730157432,
2.74258785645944,3.42962398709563,4.11664024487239,4.80291804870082,5.48910913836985,
6.07586072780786,6.66254162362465,7.25024515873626,7.83806196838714),.UNSPECIFIED.);
#935=CARTESIAN_POINT('',(12.9964083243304,-2.55400201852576,26.7871792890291));
#936=VERTEX_POINT('',#935);
#937=EDGE_CURVE('E322',#936,#247,#934,.T.);
#938=ORIENTED_EDGE('',*,*,#937,.F.);
#939=CARTESIAN_POINT('',(12.9962083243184,-2.55398166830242,26.7871327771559));
#940=CARTESIAN_POINT('',(13.5586098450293,-2.61120664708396,26.9179274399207));
#941=CARTESIAN_POINT('',(14.1188767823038,-2.66821442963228,27.056902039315));
#942=CARTESIAN_POINT('',(15.2351414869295,-2.78179560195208,27.3512111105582));
#943=CARTESIAN_POINT('',(15.791139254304,-2.83836899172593,27.5065455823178));
#944=CARTESIAN_POINT('',(16.3450024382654,-2.89472518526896,27.6700599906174));
#945=B_SPLINE_CURVE_WITH_KNOTS('',3,(#939,#940,#941,#942,#943,#944),.UNSPECIFIED.,.F.,.F.,(4,2,
4),(0.,1.74016258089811,3.48032515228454),.UNSPECIFIED.);
#946=EDGE_CURVE('E245',#936,#512,#945,.T.);
#947=ORIENTED_EDGE('',*,*,#946,.T.);
#948=ORIENTED_EDGE('',*,*,#515,.T.);
#949=CARTESIAN_POINT('',(13.1526156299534,2.57444288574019,26.8239357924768));
#950=CARTESIAN_POINT('',(13.6884788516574,2.6287942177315,26.9500907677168));
#951=CARTESIAN_POINT('',(14.2223917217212,2.68294773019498,27.0836786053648));
#952=CARTESIAN_POINT('',(15.2863167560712,2.79085911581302,27.3657200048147));
#953=CARTESIAN_POINT('',(15.8163289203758,2.84461698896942,27.5141735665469));
#954=CARTESIAN_POINT('',(16.3443907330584,2.89817704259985,27.6700599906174));
#955=B_SPLINE_CURVE_WITH_KNOTS('',3,(#949,#950,#951,#952,#953,#954),.UNSPECIFIED.,.F.,.F.,(4,2,
4),(0.,1.65908751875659,3.31817502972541),.UNSPECIFIED.);
#956=CARTESIAN_POINT('',(13.1528156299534,2.57446317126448,26.8239828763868));
#957=VERTEX_POINT('',#956);
#958=EDGE_CURVE('E276',#957,#514,#955,.T.);
#959=ORIENTED_EDGE('',*,*,#958,.F.);
#960=CARTESIAN_POINT('',(6.024532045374,5.26355694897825,25.8131364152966));
#961=CARTESIAN_POINT('',(6.16690476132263,5.09913304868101,25.8129971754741));
#962=CARTESIAN_POINT('',(6.31601972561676,4.94055485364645,25.8153541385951));
#963=CARTESIAN_POINT('',(6.62655584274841,4.63614521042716,25.8250027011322));
#964=CARTESIAN_POINT('',(6.7879754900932,4.49031220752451,25.8322936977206));
#965=CARTESIAN_POINT('',(7.12145474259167,4.21284299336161,25.8517220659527));
#966=CARTESIAN_POINT('',(7.29347942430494,4.08116373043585,25.8638441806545));
#967=CARTESIAN_POINT('',(7.64736462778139,3.83234945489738,25.8928251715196));
#968=CARTESIAN_POINT('',(7.82922517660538,3.71521448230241,25.9096840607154));
#969=CARTESIAN_POINT('',(8.20178776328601,3.49604471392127,25.9480287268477));
#970=CARTESIAN_POINT('',(8.39250457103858,3.39403642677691,25.9695224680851));
#971=CARTESIAN_POINT('',(8.78119845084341,3.20593098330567,26.0169529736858));
#972=CARTESIAN_POINT('',(8.97917867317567,3.11984083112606,26.0428916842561));
#973=CARTESIAN_POINT('',(9.38110362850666,2.96402714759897,26.0990271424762));
#974=CARTESIAN_POINT('',(9.58505370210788,2.89431880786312,26.1292278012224));
#975=CARTESIAN_POINT('',(9.99723627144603,2.77173272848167,26.1936263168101));
#976=CARTESIAN_POINT('',(10.2054670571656,2.71884840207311,26.2278226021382));
#977=CARTESIAN_POINT('',(10.641032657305,2.62666034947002,26.3027536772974));
#978=CARTESIAN_POINT('',(10.8686042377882,2.58871528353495,26.3437891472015));
#979=CARTESIAN_POINT('',(11.325443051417,2.5326356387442,26.4298927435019));
#980=CARTESIAN_POINT('',(11.5547105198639,2.51450386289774,26.4749614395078));
#981=CARTESIAN_POINT('',(12.0133084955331,2.49800092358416,26.5687996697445));
#982=CARTESIAN_POINT('',(12.242638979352,2.49963935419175,26.6175709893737));
#983=CARTESIAN_POINT('',(12.6995448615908,2.5224660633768,26.7184151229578));
#984=CARTESIAN_POINT('',(12.9271206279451,2.54365012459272,26.770487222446));
#985=CARTESIAN_POINT('',(13.1530156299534,2.5744904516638,26.8240302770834));
#986=B_SPLINE_CURVE_WITH_KNOTS('',3,(#960,#961,#962,#963,#964,#965,#966,#967,#968,#969,#970,
#971,#972,#973,#974,#975,#976,#977,#978,#979,#980,#981,#982,#983,#984,#985),.UNSPECIFIED.,.F.,
.F.,(4,2,2,2,2,2,2,2,2,2,2,2,4),(0.,0.652287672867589,1.3044956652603,1.95466006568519,
2.60482625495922,3.25611868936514,3.90769702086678,4.55987722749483,5.21180178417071,
5.91390661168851,6.61611075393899,7.31865567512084,8.02104904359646),.UNSPECIFIED.);
#987=EDGE_CURVE('E261',#216,#957,#986,.T.);
#988=ORIENTED_EDGE('',*,*,#987,.F.);
#989=ORIENTED_EDGE('',*,*,#217,.T.);
#990=CARTESIAN_POINT('',(-6.02453204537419,5.26355694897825,25.8131364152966));
#991=CARTESIAN_POINT('',(-6.1669047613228,5.099133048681,25.8129971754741));
#992=CARTESIAN_POINT('',(-6.31601972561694,4.94055485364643,25.8153541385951));
#993=CARTESIAN_POINT('',(-6.62655584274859,4.63614521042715,25.8250027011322));
#994=CARTESIAN_POINT('',(-6.78797549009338,4.4903122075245,25.8322936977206));
#995=CARTESIAN_POINT('',(-7.12145474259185,4.21284299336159,25.8517220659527));
#996=CARTESIAN_POINT('',(-7.29347942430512,4.08116373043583,25.8638441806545));
#997=CARTESIAN_POINT('',(-7.64736462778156,3.83234945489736,25.8928251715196));
#998=CARTESIAN_POINT('',(-7.82922517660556,3.71521448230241,25.9096840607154));
#999=CARTESIAN_POINT('',(-8.20178776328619,3.49604471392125,25.9480287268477));
#1000=CARTESIAN_POINT('',(-8.39250457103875,3.39403642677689,25.9695224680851));
#1001=CARTESIAN_POINT('',(-8.78119845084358,3.20593098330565,26.0169529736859));
#1002=CARTESIAN_POINT('',(-8.97917867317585,3.11984083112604,26.0428916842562));
#1003=CARTESIAN_POINT('',(-9.38110362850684,2.96402714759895,26.0990271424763));
#1004=CARTESIAN_POINT('',(-9.58505370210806,2.89431880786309,26.1292278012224));
#1005=CARTESIAN_POINT('',(-9.99723627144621,2.77173272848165,26.1936263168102));
#1006=CARTESIAN_POINT('',(-10.2054670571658,2.7188484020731,26.2278226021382));
#1007=CARTESIAN_POINT('',(-10.6410326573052,2.62666034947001,26.3027536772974));
#1008=CARTESIAN_POINT('',(-10.8686042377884,2.58871528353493,26.3437891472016));
#1009=CARTESIAN_POINT('',(-11.3254430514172,2.53263563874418,26.4298927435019));
#1010=CARTESIAN_POINT('',(-11.5547105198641,2.51450386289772,26.4749614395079));
#1011=CARTESIAN_POINT('',(-12.0133084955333,2.49800092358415,26.5687996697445));
#1012=CARTESIAN_POINT('',(-12.2426389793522,2.49963935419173,26.6175709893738));
#1013=CARTESIAN_POINT('',(-12.699544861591,2.52246606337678,26.7184151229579));
#1014=CARTESIAN_POINT('',(-12.9271206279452,2.54365012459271,26.7704872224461));
#1015=CARTESIAN_POINT('',(-13.1530156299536,2.57449045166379,26.8240302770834));
#1016=B_SPLINE_CURVE_WITH_KNOTS('',3,(#990,#991,#992,#993,#994,#995,#996,#997,#998,#999,#1000,
#1001,#1002,#1003,#1004,#1005,#1006,#1007,#1008,#1009,#1010,#1011,#1012,#1013,#1014,#1015),
.UNSPECIFIED.,.F.,.F.,(4,2,2,2,2,2,2,2,2,2,2,2,4),(0.,0.65228767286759,1.3044956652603,
1.95466006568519,2.60482625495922,3.25611868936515,3.90769702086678,4.55987722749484,
5.21180178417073,5.91390661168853,6.61611075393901,7.31865567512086,8.02104904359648),.UNSPECIFIED.);
#1017=CARTESIAN_POINT('',(-13.1528156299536,2.57446317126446,26.8239828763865));
#1018=VERTEX_POINT('',#1017);
#1019=EDGE_CURVE('E213',#207,#1018,#1016,.T.);
#1020=ORIENTED_EDGE('',*,*,#1019,.T.);
#1021=CARTESIAN_POINT('',(-13.1526156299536,2.57444288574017,26.8239357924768));
#1022=CARTESIAN_POINT('',(-13.6884788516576,2.62879421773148,26.9500907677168));
#1023=CARTESIAN_POINT('',(-14.2223917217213,2.68294773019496,27.0836786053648));
#1024=CARTESIAN_POINT('',(-15.2863167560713,2.79085911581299,27.3657200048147));
#1025=CARTESIAN_POINT('',(-15.8163289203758,2.8446169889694,27.5141735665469));
#1026=CARTESIAN_POINT('',(-16.3443907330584,2.89817704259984,27.6700599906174));
#1027=B_SPLINE_CURVE_WITH_KNOTS('',3,(#1021,#1022,#1023,#1024,#1025,#1026),.UNSPECIFIED.,.F.,
.F.,(4,2,4),(0.,1.6590875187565,3.31817502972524),.UNSPECIFIED.);
#1028=EDGE_CURVE('E156',#1018,#700,#1027,.T.);
#1029=ORIENTED_EDGE('',*,*,#1028,.T.);
#1030=ORIENTED_EDGE('',*,*,#703,.T.);
#1031=CARTESIAN_POINT('',(-12.9962083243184,-2.55398166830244,26.7871327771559));
#1032=CARTESIAN_POINT('',(-13.5586098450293,-2.61120664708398,26.9179274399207));
#1033=CARTESIAN_POINT('',(-14.1188767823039,-2.6682144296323,27.056902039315));
#1034=CARTESIAN_POINT('',(-15.2351414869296,-2.7817956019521,27.3512111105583));
#1035=CARTESIAN_POINT('',(-15.7911392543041,-2.83836899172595,27.5065455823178));
#1036=CARTESIAN_POINT('',(-16.3450024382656,-2.89472518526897,27.6700599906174));
#1037=B_SPLINE_CURVE_WITH_KNOTS('',3,(#1031,#1032,#1033,#1034,#1035,#1036),.UNSPECIFIED.,.F.,
.F.,(4,2,4),(0.,1.7401625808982,3.48032515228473),.UNSPECIFIED.);
#1038=CARTESIAN_POINT('',(-12.996408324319,-2.55400201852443,26.7871792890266));
#1039=VERTEX_POINT('',#1038);
#1040=EDGE_CURVE('E278',#1039,#702,#1037,.T.);
#1041=ORIENTED_EDGE('',*,*,#1040,.F.);
#1042=CARTESIAN_POINT('',(-12.9966083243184,-2.55402529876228,26.7872259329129));
#1043=CARTESIAN_POINT('',(-12.7754529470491,-2.52825709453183,26.7356435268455));
#1044=CARTESIAN_POINT('',(-12.5528725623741,-2.5117272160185,26.6855038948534));
#1045=CARTESIAN_POINT('',(-12.1063783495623,-2.49733345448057,26.5884436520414));
#1046=CARTESIAN_POINT('',(-11.8824643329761,-2.49947227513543,26.5415235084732));
#1047=CARTESIAN_POINT('',(-11.4348095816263,-2.52261669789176,26.4512357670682));
#1048=CARTESIAN_POINT('',(-11.2110689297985,-2.54362860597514,26.4078693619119));
#1049=CARTESIAN_POINT('',(-10.7654590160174,-2.60455176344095,26.3250334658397));
#1050=CARTESIAN_POINT('',(-10.5435896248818,-2.64446169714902,26.2855637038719));
#1051=CARTESIAN_POINT('',(-10.1029278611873,-2.74316372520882,26.2107549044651));
#1052=CARTESIAN_POINT('',(-9.88414203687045,-2.80199107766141,26.1754237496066));
#1053=CARTESIAN_POINT('',(-9.45174044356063,-2.93823754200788,26.1092665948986));
#1054=CARTESIAN_POINT('',(-9.23812452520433,-3.01565611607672,26.0784404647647));
#1055=CARTESIAN_POINT('',(-8.81794496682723,-3.18856082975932,26.0215849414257));
#1056=CARTESIAN_POINT('',(-8.6113739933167,-3.28402745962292,25.9955504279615));
#1057=CARTESIAN_POINT('',(-8.20669244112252,-3.49247951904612,25.948470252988));
#1058=CARTESIAN_POINT('',(-8.0085807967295,-3.6054627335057,25.9274239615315));
#1059=CARTESIAN_POINT('',(-7.65039872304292,-3.83057518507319,25.8931881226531));
#1060=CARTESIAN_POINT('',(-7.48897596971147,-3.94045548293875,25.8793019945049));
#1061=CARTESIAN_POINT('',(-7.17442939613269,-4.17187167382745,25.8554138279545));
#1062=CARTESIAN_POINT('',(-7.02130457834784,-4.29340616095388,25.8454113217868));
#1063=CARTESIAN_POINT('',(-6.72399395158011,-4.5476994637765,25.8293490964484));
#1064=CARTESIAN_POINT('',(-6.57982418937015,-4.68047747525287,25.823296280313));
#1065=CARTESIAN_POINT('',(-6.30152732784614,-4.9563354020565,25.8151989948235));
#1066=CARTESIAN_POINT('',(-6.16740216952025,-5.09941729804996,25.8131552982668));
#1067=CARTESIAN_POINT('',(-6.03873367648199,-5.24725563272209,25.8131362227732));
#1068=B_SPLINE_CURVE_WITH_KNOTS('',3,(#1042,#1043,#1044,#1045,#1046,#1047,#1048,#1049,#1050,
#1051,#1052,#1053,#1054,#1055,#1056,#1057,#1058,#1059,#1060,#1061,#1062,#1063,#1064,#1065,#1066,
#1067),.UNSPECIFIED.,.F.,.F.,(4,2,2,2,2,2,2,2,2,2,2,2,4),(0.,0.6854698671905,1.37103900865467,
2.05683730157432,2.74258785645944,3.42962398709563,4.1166402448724,4.80291804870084,
5.48910913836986,6.07586072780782,6.66254162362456,7.25024515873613,7.83806196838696),.UNSPECIFIED.);
#1069=EDGE_CURVE('E314',#1039,#256,#1068,.T.);
#1070=ORIENTED_EDGE('',*,*,#1069,.T.);
#1071=ORIENTED_EDGE('',*,*,#257,.T.);
#1072=EDGE_LOOP('',(#938,#947,#948,#959,#988,#989,#1020,#1029,#1030,#1041,#1070,#1071));
#1073=FACE_BOUND('',#1072,.T.);
#1074=ADVANCED_FACE('F273',(#907,#1073),#896,.T.);
#1075=CARTESIAN_POINT('',(0.,0.,19.55));
#1076=DIRECTION('',(0.,-1.,0.));
#1077=DIRECTION('',(1.,0.,0.));
#1078=AXIS2_PLACEMENT_3D('',#1075,#1076,#1077);
#1079=SPHERICAL_SURFACE('',#1078,8.45);
#1080=CARTESIAN_POINT('',(0.,0.,19.55));
#1081=DIRECTION('',(0.,0.,1.));
#1082=DIRECTION('',(0.,-1.,0.));
#1083=AXIS2_PLACEMENT_3D('',#1080,#1081,#1082);
#1084=SPHERICAL_SURFACE('',#1083,8.45);
#1085=ORIENTED_EDGE('',*,*,#904,.T.);
#1086=EDGE_LOOP('',(#1085));
#1087=FACE_BOUND('',#1086,.T.);
#1088=ADVANCED_FACE('F16',(#1087),#1084,.T.);
#1089=CARTESIAN_POINT('',(3.,0.,18.));
#1090=DIRECTION('',(0.,0.,-1.));
#1091=DIRECTION('',(0.,1.,0.));
#1092=AXIS2_PLACEMENT_3D('',#1089,#1090,#1091);
#1093=PLANE('',#1092);
#1094=CARTESIAN_POINT('',(0.,0.,18.));
#1095=DIRECTION('',(0.,0.,1.));
#1096=DIRECTION('',(0.,-1.,0.));
#1097=AXIS2_PLACEMENT_3D('',#1094,#1095,#1096);
#1098=CIRCLE('',#1097,3.);
#1099=CARTESIAN_POINT('',(0.,-3.,18.));
#1100=VERTEX_POINT('',#1099);
#1101=EDGE_CURVE('E272',#1100,#1100,#1098,.T.);
#1102=ORIENTED_EDGE('',*,*,#1101,.F.);
#1103=EDGE_LOOP('',(#1102));
#1104=FACE_BOUND('',#1103,.T.);
#1105=ADVANCED_FACE('F430',(#1104),#1093,.T.);
#1106=CARTESIAN_POINT('',(0.,0.,32.9780362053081));
#1107=DIRECTION('',(0.,0.,1.));
#1108=DIRECTION('',(0.,-1.,0.));
#1109=AXIS2_PLACEMENT_3D('',#1106,#1107,#1108);
#1110=CYLINDRICAL_SURFACE('',#1109,3.);
#1111=ORIENTED_EDGE('',*,*,#159,.F.);
#1112=EDGE_LOOP('',(#1111));
#1113=FACE_BOUND('',#1112,.T.);
#1114=ORIENTED_EDGE('',*,*,#1101,.T.);
#1115=EDGE_LOOP('',(#1114));
#1116=FACE_BOUND('',#1115,.T.);
#1117=ADVANCED_FACE('F428',(#1113,#1116),#1110,.F.);
#1118=CARTESIAN_POINT('',(-5.40816196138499,-6.07467861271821,7.7482771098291));
#1119=CARTESIAN_POINT('',(-5.52938177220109,-5.8920562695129,7.74173743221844));
#1120=CARTESIAN_POINT('',(-5.65818351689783,-5.7143974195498,7.73727619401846));
#1121=CARTESIAN_POINT('',(-5.92995209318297,-5.37022086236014,7.73249766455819));
#1122=CARTESIAN_POINT('',(-6.07291819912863,-5.20370258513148,7.73218016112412));
#1123=CARTESIAN_POINT('',(-6.37194671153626,-4.88309096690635,7.73567453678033));
#1124=CARTESIAN_POINT('',(-6.52800183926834,-4.72899081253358,7.73948413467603));
#1125=CARTESIAN_POINT('',(-6.85214571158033,-4.43419295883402,7.75127335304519));
#1126=CARTESIAN_POINT('',(-7.02023433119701,-4.29349512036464,7.75925293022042));
#1127=CARTESIAN_POINT('',(-7.36787685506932,-4.02597472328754,7.77949081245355));
#1128=CARTESIAN_POINT('',(-7.54747132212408,-3.89920607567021,7.79176502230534));
#1129=CARTESIAN_POINT('',(-7.91623418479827,-3.66101233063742,7.82066267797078));
#1130=CARTESIAN_POINT('',(-8.10540276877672,-3.54958753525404,7.83728620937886));
#1131=CARTESIAN_POINT('',(-8.4918073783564,-3.34286928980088,7.8749252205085));
#1132=CARTESIAN_POINT('',(-8.68903906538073,-3.24756730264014,7.89593836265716));
#1133=CARTESIAN_POINT('',(-9.0902072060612,-3.07361055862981,7.94237123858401));
#1134=CARTESIAN_POINT('',(-9.29414361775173,-2.99495569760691,7.96779094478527));
#1135=CARTESIAN_POINT('',(-9.70728411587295,-2.85471488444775,8.02299934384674));
#1136=CARTESIAN_POINT('',(-9.91648954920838,-2.79313334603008,8.05278916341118));
#1137=CARTESIAN_POINT('',(-10.3386977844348,-2.68733665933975,8.11664426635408));
#1138=CARTESIAN_POINT('',(-10.5517021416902,-2.64312880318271,8.15071133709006));
#1139=CARTESIAN_POINT('',(-10.9800978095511,-2.57223450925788,8.2229850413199));
#1140=CARTESIAN_POINT('',(-11.1954909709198,-2.54556278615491,8.26119511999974));
#1141=CARTESIAN_POINT('',(-11.6269140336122,-2.50981645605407,8.34150952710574));
#1142=CARTESIAN_POINT('',(-11.8429436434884,-2.50073476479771,8.38361228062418));
#1143=CARTESIAN_POINT('',(-12.2789655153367,-2.50002106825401,8.4724337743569));
#1144=CARTESIAN_POINT('',(-12.4989420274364,-2.50877204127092,8.51923286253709));
#1145=CARTESIAN_POINT('',(-12.9366686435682,-2.54424452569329,8.61635812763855));
#1146=CARTESIAN_POINT('',(-13.154418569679,-2.57096746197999,8.6666845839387));
#1147=CARTESIAN_POINT('',(-13.5860522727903,-2.64199093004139,8.77048849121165));
#1148=CARTESIAN_POINT('',(-13.7999393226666,-2.6862757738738,8.82396309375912));
#1149=CARTESIAN_POINT('',(-14.2226717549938,-2.79192997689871,8.93374204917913));
#1150=CARTESIAN_POINT('',(-14.4315179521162,-2.85329655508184,8.99004594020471));
#1151=CARTESIAN_POINT('',(-14.6371915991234,-2.92296463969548,9.04759234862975));
#1152=B_SPLINE_CURVE_WITH_KNOTS('',3,(#1118,#1119,#1120,#1121,#1122,#1123,#1124,#1125,#1126,
#1127,#1128,#1129,#1130,#1131,#1132,#1133,#1134,#1135,#1136,#1137,#1138,#1139,#1140,#1141,#1142,
#1143,#1144,#1145,#1146,#1147,#1148,#1149,#1150,#1151),.UNSPECIFIED.,.F.,.F.,(4,2,2,2,2,2,2,2,2,
2,2,2,2,2,2,2,4),(0.,0.657668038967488,1.31530240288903,1.97257345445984,2.62983768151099,
3.28956225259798,3.94929980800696,4.60868692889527,5.26806992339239,5.9276232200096,
6.5874530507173,7.24783584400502,7.90795261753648,8.5823955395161,9.25689194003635,
9.93078716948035,10.6045727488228),.UNSPECIFIED.);
#1153=CARTESIAN_POINT('',(-12.9964083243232,-2.55400201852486,8.63070434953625));
#1154=VERTEX_POINT('',#1153);
#1155=EDGE_CURVE('E502',#1154,#316,#1152,.F.);
#1156=ORIENTED_EDGE('',*,*,#1155,.F.);
#1157=CARTESIAN_POINT('',(-12.9962083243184,-2.55398166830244,8.63065853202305));
#1158=CARTESIAN_POINT('',(-13.7943446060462,-2.63519292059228,8.81347846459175));
#1159=CARTESIAN_POINT('',(-14.5877985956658,-2.71592774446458,9.01694513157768));
#1160=CARTESIAN_POINT('',(-16.1611919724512,-2.87602226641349,9.46398142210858));
#1161=CARTESIAN_POINT('',(-16.9411614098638,-2.95538502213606,9.7074441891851));
#1162=CARTESIAN_POINT('',(-18.4876557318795,-3.11274253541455,10.234250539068));
#1163=CARTESIAN_POINT('',(-19.2541805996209,-3.19073729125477,10.5175941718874));
#1164=CARTESIAN_POINT('',(-20.7737763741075,-3.34535784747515,11.1241962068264));
#1165=CARTESIAN_POINT('',(-21.5268064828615,-3.42197949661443,11.4475578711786));
#1166=CARTESIAN_POINT('',(-22.2710561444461,-3.4977077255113,11.7901956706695));
#1167=B_SPLINE_CURVE_WITH_KNOTS('',3,(#1157,#1158,#1159,#1160,#1161,#1162,#1163,#1164,#1165,
#1166),.UNSPECIFIED.,.F.,.F.,(4,2,2,2,4),(0.,2.46819948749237,4.92990890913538,7.39162141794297,
9.85982400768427),.UNSPECIFIED.);
#1168=EDGE_CURVE('E480',#1154,#797,#1167,.T.);
#1169=ORIENTED_EDGE('',*,*,#1168,.T.);
#1170=ORIENTED_EDGE('',*,*,#798,.F.);
#1171=CARTESIAN_POINT('',(-13.1526156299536,2.57444288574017,8.66696966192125));
#1172=CARTESIAN_POINT('',(-13.9370340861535,2.65400458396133,8.84943351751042));
#1173=CARTESIAN_POINT('',(-14.716856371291,2.73310010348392,9.05185397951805));
#1174=CARTESIAN_POINT('',(-16.2633623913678,2.88995853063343,9.49546553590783));
#1175=CARTESIAN_POINT('',(-17.0300745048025,2.96772431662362,9.73655668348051));
#1176=CARTESIAN_POINT('',(-18.5504261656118,3.12192996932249,10.2573018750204));
#1177=CARTESIAN_POINT('',(-19.3040656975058,3.19836983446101,10.5369559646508));
#1178=CARTESIAN_POINT('',(-20.7982632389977,3.34992273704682,11.134858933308));
#1179=CARTESIAN_POINT('',(-21.5387829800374,3.42503189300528,11.453204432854));
#1180=CARTESIAN_POINT('',(-22.2708092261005,3.49927957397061,11.7901956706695));
#1181=B_SPLINE_CURVE_WITH_KNOTS('',3,(#1171,#1172,#1173,#1174,#1175,#1176,#1177,#1178,#1179,
#1180),.UNSPECIFIED.,.F.,.F.,(4,2,2,2,4),(0.,2.42758220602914,4.848988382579,7.27039742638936,
9.6979825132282),.UNSPECIFIED.);
#1182=CARTESIAN_POINT('',(-13.1528156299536,2.57446317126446,8.66701618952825));
#1183=VERTEX_POINT('',#1182);
#1184=EDGE_CURVE('E468',#1183,#793,#1181,.T.);
#1185=ORIENTED_EDGE('',*,*,#1184,.F.);
#1186=CARTESIAN_POINT('',(-5.40789714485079,6.07461400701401,7.74825077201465));
#1187=CARTESIAN_POINT('',(-5.52917736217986,5.89198502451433,7.74171502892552));
#1188=CARTESIAN_POINT('',(-5.65803975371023,5.71432205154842,7.73725822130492));
#1189=CARTESIAN_POINT('',(-5.92992964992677,5.37014226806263,7.73248959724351));
#1190=CARTESIAN_POINT('',(-6.07295642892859,5.20362488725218,7.73217756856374));
#1191=CARTESIAN_POINT('',(-6.37210580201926,4.88302009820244,7.73568398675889));
#1192=CARTESIAN_POINT('',(-6.52822111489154,4.72892587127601,7.73950015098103));
#1193=CARTESIAN_POINT('',(-6.8524844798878,4.43414479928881,7.75130368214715));
#1194=CARTESIAN_POINT('',(-7.02063240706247,4.29345781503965,7.75929100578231));
#1195=CARTESIAN_POINT('',(-7.36839276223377,4.02596374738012,7.77954568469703));
#1196=CARTESIAN_POINT('',(-7.54804576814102,3.89921061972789,7.79182895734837));
#1197=CARTESIAN_POINT('',(-7.91692396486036,3.66105266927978,7.82074605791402));
#1198=CARTESIAN_POINT('',(-8.10614934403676,3.54964814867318,7.83737997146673));
#1199=CARTESIAN_POINT('',(-8.49266533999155,3.34297499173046,7.87504105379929));
#1200=CARTESIAN_POINT('',(-8.68995161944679,3.24769781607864,7.89606588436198));
#1201=CARTESIAN_POINT('',(-9.0912263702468,3.07379499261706,7.94252339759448));
#1202=CARTESIAN_POINT('',(-9.29521479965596,2.9951692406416,7.96795605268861));
#1203=CARTESIAN_POINT('',(-9.70845663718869,2.85499058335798,8.02319155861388));
#1204=CARTESIAN_POINT('',(-9.91771139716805,2.7934421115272,8.05299554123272));
#1205=CARTESIAN_POINT('',(-10.3400150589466,2.68771529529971,8.11688005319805));
#1206=CARTESIAN_POINT('',(-10.5530655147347,2.64354424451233,8.15096237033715));
#1207=CARTESIAN_POINT('',(-10.9815499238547,2.57272696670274,8.22326754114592));
#1208=CARTESIAN_POINT('',(-11.1969857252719,2.54609545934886,8.2614938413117));
#1209=CARTESIAN_POINT('',(-11.6284903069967,2.5104325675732,8.34184151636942));
#1210=CARTESIAN_POINT('',(-11.844558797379,2.50139409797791,8.38396131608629));
#1211=CARTESIAN_POINT('',(-12.2806577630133,2.50077046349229,8.47281848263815));
#1212=CARTESIAN_POINT('',(-12.5006723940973,2.50956853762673,8.51963625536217));
#1213=CARTESIAN_POINT('',(-12.9384709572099,2.54513800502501,8.6167995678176));
#1214=CARTESIAN_POINT('',(-13.156254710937,2.57191082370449,8.66714538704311));
#1215=CARTESIAN_POINT('',(-13.5879515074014,2.64303637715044,8.77098851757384));
#1216=CARTESIAN_POINT('',(-13.8018678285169,2.68737341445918,8.82448297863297));
#1217=CARTESIAN_POINT('',(-14.2246542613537,2.79313397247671,8.93430204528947));
#1218=CARTESIAN_POINT('',(-14.4335251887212,2.85455471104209,8.99062618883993));
#1219=CARTESIAN_POINT('',(-14.6392212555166,2.92427775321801,9.04819298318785));
#1220=B_SPLINE_CURVE_WITH_KNOTS('',3,(#1186,#1187,#1188,#1189,#1190,#1191,#1192,#1193,#1194,
#1195,#1196,#1197,#1198,#1199,#1200,#1201,#1202,#1203,#1204,#1205,#1206,#1207,#1208,#1209,#1210,
#1211,#1212,#1213,#1214,#1215,#1216,#1217,#1218,#1219),.UNSPECIFIED.,.F.,.F.,(4,2,2,2,2,2,2,2,2,
2,2,2,2,2,2,2,4),(0.,0.65778442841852,1.31553517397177,1.9729224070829,2.63030281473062,
3.29014521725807,3.95000060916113,4.60950551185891,5.26900628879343,5.92867812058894,
6.58862653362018,7.24912809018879,7.90936359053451,8.58393530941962,9.25856052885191,
9.93258417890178,10.6064981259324),.UNSPECIFIED.);
#1221=EDGE_CURVE('E182',#320,#1183,#1220,.T.);
#1222=ORIENTED_EDGE('',*,*,#1221,.F.);
#1223=ORIENTED_EDGE('',*,*,#321,.T.);
#1224=EDGE_LOOP('',(#1156,#1169,#1170,#1185,#1222,#1223));
#1225=FACE_BOUND('',#1224,.T.);
#1226=ADVANCED_FACE('F197',(#1225),#381,.T.);
#1227=CARTESIAN_POINT('',(13.1528156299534,2.57446317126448,-7.02196379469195));
#1228=DIRECTION('',(0.100909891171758,-0.994895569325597,0.));
#1229=DIRECTION('',(0.994895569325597,0.100909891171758,0.));
#1230=AXIS2_PLACEMENT_3D('',#1227,#1228,#1229);
#1231=PLANE('',#1230);
#1232=DIRECTION('',(0.,0.,1.));
#1233=VECTOR('',#1232,1.);
#1234=CARTESIAN_POINT('',(13.1528156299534,2.57446317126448,-7.02196379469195));
#1235=LINE('',#1234,#1233);
#1236=CARTESIAN_POINT('',(13.1528156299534,2.57446317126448,18.2481040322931));
#1237=VERTEX_POINT('',#1236);
#1238=EDGE_CURVE('E179',#419,#1237,#1235,.T.);
#1239=ORIENTED_EDGE('',*,*,#1238,.T.);
#1240=CARTESIAN_POINT('',(18.9983287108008,3.1673596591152,19.5161101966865));
#1241=DIRECTION('',(0.100909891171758,-0.994895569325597,0.));
#1242=DIRECTION('',(0.994895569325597,0.100909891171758,0.));
#1243=AXIS2_PLACEMENT_3D('',#1240,#1241,#1242);
#1244=CIRCLE('',#1243,6.01077275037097);
#1245=CARTESIAN_POINT('',(13.1528156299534,2.57446317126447,20.7841163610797));
#1246=VERTEX_POINT('',#1245);
#1247=EDGE_CURVE('E34',#1237,#1246,#1244,.T.);
#1248=ORIENTED_EDGE('',*,*,#1247,.T.);
#1249=EDGE_CURVE('E178',#1246,#957,#1235,.T.);
#1250=ORIENTED_EDGE('',*,*,#1249,.T.);
#1251=ORIENTED_EDGE('',*,*,#958,.T.);
#1252=ORIENTED_EDGE('',*,*,#694,.F.);
#1253=ORIENTED_EDGE('',*,*,#435,.F.);
#1254=EDGE_LOOP('',(#1239,#1248,#1250,#1251,#1252,#1253));
#1255=FACE_BOUND('',#1254,.T.);
#1256=ADVANCED_FACE('F204',(#1255),#1231,.F.);
#1257=CARTESIAN_POINT('',(-12.0717114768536,10.5010774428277,-7.02196379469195));
#1258=DIRECTION('',(0.,0.,1.));
#1259=DIRECTION('',(0.,-1.,0.));
#1260=AXIS2_PLACEMENT_3D('',#1257,#1258,#1259);
#1261=CYLINDRICAL_SURFACE('',#1260,8.);
#1262=CARTESIAN_POINT('',(-13.1530156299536,2.57449045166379,20.7851435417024));
#1263=CARTESIAN_POINT('',(-13.1325676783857,2.57170354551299,20.6802002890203));
#1264=CARTESIAN_POINT('',(-13.1144634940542,2.56931150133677,20.5747959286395));
#1265=CARTESIAN_POINT('',(-13.0832029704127,2.56526374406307,20.3632225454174));
#1266=CARTESIAN_POINT('',(-13.0700476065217,2.56360817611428,20.2570533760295));
#1267=CARTESIAN_POINT('',(-13.038618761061,2.55969394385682,19.9398433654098));
#1268=CARTESIAN_POINT('',(-13.027960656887,2.55843383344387,19.7279767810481));
#1269=CARTESIAN_POINT('',(-13.027960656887,2.55843383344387,19.3042436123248));
#1270=CARTESIAN_POINT('',(-13.038618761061,2.55969394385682,19.0923770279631));
#1271=CARTESIAN_POINT('',(-13.0700476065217,2.56360817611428,18.7751670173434));
#1272=CARTESIAN_POINT('',(-13.0832029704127,2.56526374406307,18.6689978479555));
#1273=CARTESIAN_POINT('',(-13.1144634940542,2.56931150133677,18.4574244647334));
#1274=CARTESIAN_POINT('',(-13.1325676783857,2.57170354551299,18.3520201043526));
#1275=CARTESIAN_POINT('',(-13.1530156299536,2.57449045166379,18.2470768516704));
#1276=B_SPLINE_CURVE_WITH_KNOTS('',3,(#1262,#1263,#1264,#1265,#1266,#1267,#1268,#1269,#1270,
#1271,#1272,#1273,#1274,#1275),.UNSPECIFIED.,.F.,.F.,(4,2,2,2,2,2,4),(0.,0.320814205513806,
0.641691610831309,1.27697796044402,1.91226431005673,2.23314171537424,2.55395592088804),.UNSPECIFIED.);
#1277=CARTESIAN_POINT('',(-13.1528156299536,2.57446317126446,20.7841163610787));
#1278=VERTEX_POINT('',#1277);
#1279=CARTESIAN_POINT('',(-13.1528156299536,2.57446317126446,18.2481040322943));
#1280=VERTEX_POINT('',#1279);
#1281=EDGE_CURVE('E27',#1278,#1280,#1276,.T.);
#1282=ORIENTED_EDGE('',*,*,#1281,.F.);
#1283=DIRECTION('',(0.,0.,1.));
#1284=VECTOR('',#1283,1.);
#1285=CARTESIAN_POINT('',(-13.1528156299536,2.57446317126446,-7.02196379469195));
#1286=LINE('',#1285,#1284);
#1287=EDGE_CURVE('E149',#1278,#1018,#1286,.T.);
#1288=ORIENTED_EDGE('',*,*,#1287,.T.);
#1289=ORIENTED_EDGE('',*,*,#1019,.F.);
#1290=ORIENTED_EDGE('',*,*,#208,.F.);
#1291=ORIENTED_EDGE('',*,*,#190,.F.);
#1292=ORIENTED_EDGE('',*,*,#235,.T.);
#1293=ORIENTED_EDGE('',*,*,#372,.F.);
#1294=ORIENTED_EDGE('',*,*,#1221,.T.);
#1295=EDGE_CURVE('E151',#1183,#1280,#1286,.T.);
#1296=ORIENTED_EDGE('',*,*,#1295,.T.);
#1297=EDGE_LOOP('',(#1282,#1288,#1289,#1290,#1291,#1292,#1293,#1294,#1296));
#1298=FACE_BOUND('',#1297,.T.);
#1299=ADVANCED_FACE('F147',(#1298),#1261,.F.);
#1300=CARTESIAN_POINT('',(-13.1528156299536,2.57446317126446,-7.02196379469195));
#1301=DIRECTION('',(0.100909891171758,0.994895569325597,0.));
#1302=DIRECTION('',(-0.994895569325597,0.100909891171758,0.));
#1303=AXIS2_PLACEMENT_3D('',#1300,#1301,#1302);
#1304=PLANE('',#1303);
#1305=CARTESIAN_POINT('',(-18.9983287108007,3.16735965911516,19.5161101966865));
#1306=DIRECTION('',(0.100909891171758,0.994895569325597,0.));
#1307=DIRECTION('',(-0.994895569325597,0.100909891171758,0.));
#1308=AXIS2_PLACEMENT_3D('',#1305,#1306,#1307);
#1309=CIRCLE('',#1308,6.01077275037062);
#1310=EDGE_CURVE('E9',#1280,#1278,#1309,.T.);
#1311=ORIENTED_EDGE('',*,*,#1310,.F.);
#1312=ORIENTED_EDGE('',*,*,#1295,.F.);
#1313=ORIENTED_EDGE('',*,*,#1184,.T.);
#1314=ORIENTED_EDGE('',*,*,#794,.T.);
#1315=ORIENTED_EDGE('',*,*,#1028,.F.);
#1316=ORIENTED_EDGE('',*,*,#1287,.F.);
#1317=EDGE_LOOP('',(#1311,#1312,#1313,#1314,#1315,#1316));
#1318=FACE_BOUND('',#1317,.T.);
#1319=ADVANCED_FACE('F154',(#1318),#1304,.T.);
#1320=CARTESIAN_POINT('',(12.0717114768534,10.5010774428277,-7.02196379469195));
#1321=DIRECTION('',(0.,0.,1.));
#1322=DIRECTION('',(0.,-1.,0.));
#1323=AXIS2_PLACEMENT_3D('',#1320,#1321,#1322);
#1324=CYLINDRICAL_SURFACE('',#1323,8.);
#1325=ORIENTED_EDGE('',*,*,#1249,.F.);
#1326=CARTESIAN_POINT('',(13.1530156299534,2.57449045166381,20.7851435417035));
#1327=CARTESIAN_POINT('',(13.1325676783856,2.57170354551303,20.6802002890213));
#1328=CARTESIAN_POINT('',(13.1144634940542,2.56931150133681,20.5747959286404));
#1329=CARTESIAN_POINT('',(13.0832029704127,2.56526374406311,20.3632225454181));
#1330=CARTESIAN_POINT('',(13.0700476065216,2.56360817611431,20.2570533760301));
#1331=CARTESIAN_POINT('',(13.0386187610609,2.55969394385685,19.9398433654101));
#1332=CARTESIAN_POINT('',(13.0279606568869,2.5584338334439,19.7279767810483));
#1333=CARTESIAN_POINT('',(13.0279606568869,2.5584338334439,19.3042436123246));
#1334=CARTESIAN_POINT('',(13.0386187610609,2.55969394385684,19.0923770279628));
#1335=CARTESIAN_POINT('',(13.0700476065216,2.56360817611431,18.7751670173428));
#1336=CARTESIAN_POINT('',(13.0832029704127,2.56526374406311,18.6689978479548));
#1337=CARTESIAN_POINT('',(13.1144634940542,2.56931150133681,18.4574244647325));
#1338=CARTESIAN_POINT('',(13.1325676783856,2.57170354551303,18.3520201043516));
#1339=CARTESIAN_POINT('',(13.1530156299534,2.5744904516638,18.2470768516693));
#1340=B_SPLINE_CURVE_WITH_KNOTS('',3,(#1326,#1327,#1328,#1329,#1330,#1331,#1332,#1333,#1334,
#1335,#1336,#1337,#1338,#1339),.UNSPECIFIED.,.F.,.F.,(4,2,2,2,2,2,4),(0.,0.320814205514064,
0.641691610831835,1.27697796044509,1.91226431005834,2.23314171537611,2.55395592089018),.UNSPECIFIED.);
#1341=EDGE_CURVE('E22',#1246,#1237,#1340,.T.);
#1342=ORIENTED_EDGE('',*,*,#1341,.T.);
#1343=ORIENTED_EDGE('',*,*,#1238,.F.);
#1344=ORIENTED_EDGE('',*,*,#420,.F.);
#1345=ORIENTED_EDGE('',*,*,#94,.T.);
#1346=ORIENTED_EDGE('',*,*,#242,.F.);
#1347=ORIENTED_EDGE('',*,*,#172,.T.);
#1348=ORIENTED_EDGE('',*,*,#223,.T.);
#1349=ORIENTED_EDGE('',*,*,#987,.T.);
#1350=EDGE_LOOP('',(#1325,#1342,#1343,#1344,#1345,#1346,#1347,#1348,#1349));
#1351=FACE_BOUND('',#1350,.T.);
#1352=ADVANCED_FACE('F205',(#1351),#1324,.F.);
#1353=CARTESIAN_POINT('',(12.9964083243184,-2.55400201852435,-7.02196379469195));
#1354=DIRECTION('',(-0.101228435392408,-0.994863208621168,0.));
#1355=DIRECTION('',(0.994863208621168,-0.101228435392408,0.));
#1356=AXIS2_PLACEMENT_3D('',#1353,#1354,#1355);
#1357=PLANE('',#1356);
#1358=CARTESIAN_POINT('',(19.0039855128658,-3.16527966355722,19.5161101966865));
#1359=DIRECTION('',(-0.101228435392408,-0.994863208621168,0.));
#1360=DIRECTION('',(0.994863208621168,-0.101228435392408,0.));
#1361=AXIS2_PLACEMENT_3D('',#1358,#1359,#1360);
#1362=CIRCLE('',#1361,6.00333352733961);
#1363=CARTESIAN_POINT('',(24.9764811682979,-3.7729877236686,19.5161101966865));
#1364=VERTEX_POINT('',#1363);
#1365=EDGE_CURVE('E246',#1364,#1364,#1362,.T.);
#1366=ORIENTED_EDGE('',*,*,#1365,.F.);
#1367=EDGE_LOOP('',(#1366));
#1368=FACE_BOUND('',#1367,.T.);
#1369=DIRECTION('',(0.,0.,1.));
#1370=VECTOR('',#1369,1.);
#1371=CARTESIAN_POINT('',(12.9964083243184,-2.55400201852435,-7.02196379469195));
#1372=LINE('',#1371,#1370);
#1373=EDGE_CURVE('E175',#458,#936,#1372,.T.);
#1374=ORIENTED_EDGE('',*,*,#1373,.F.);
#1375=ORIENTED_EDGE('',*,*,#459,.T.);
#1376=ORIENTED_EDGE('',*,*,#604,.T.);
#1377=ORIENTED_EDGE('',*,*,#946,.F.);
#1378=EDGE_LOOP('',(#1374,#1375,#1376,#1377));
#1379=FACE_BOUND('',#1378,.T.);
#1380=ADVANCED_FACE('F341',(#1368,#1379),#1357,.T.);
#1381=CARTESIAN_POINT('',(-12.9964083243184,-2.55400201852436,-7.02196379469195));
#1382=DIRECTION('',(-0.101228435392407,0.994863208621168,0.));
#1383=DIRECTION('',(-0.994863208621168,-0.101228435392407,0.));
#1384=AXIS2_PLACEMENT_3D('',#1381,#1382,#1383);
#1385=PLANE('',#1384);
#1386=CARTESIAN_POINT('',(-19.0039855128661,-3.16527966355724,19.5161101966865));
#1387=DIRECTION('',(-0.101228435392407,0.994863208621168,0.));
#1388=DIRECTION('',(-0.994863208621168,-0.101228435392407,0.));
#1389=AXIS2_PLACEMENT_3D('',#1386,#1387,#1388);
#1390=CIRCLE('',#1389,6.00333352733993);
#1391=CARTESIAN_POINT('',(-24.9764811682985,-3.77298772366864,19.5161101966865));
#1392=VERTEX_POINT('',#1391);
#1393=EDGE_CURVE('E152',#1392,#1392,#1390,.T.);
#1394=ORIENTED_EDGE('',*,*,#1393,.T.);
#1395=EDGE_LOOP('',(#1394));
#1396=FACE_BOUND('',#1395,.T.);
#1397=ORIENTED_EDGE('',*,*,#1168,.F.);
#1398=DIRECTION('',(0.,0.,1.));
#1399=VECTOR('',#1398,1.);
#1400=CARTESIAN_POINT('',(-12.9964083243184,-2.55400201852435,-7.02196379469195));
#1401=LINE('',#1400,#1399);
#1402=EDGE_CURVE('E160',#1154,#1039,#1401,.T.);
#1403=ORIENTED_EDGE('',*,*,#1402,.T.);
#1404=ORIENTED_EDGE('',*,*,#1040,.T.);
#1405=ORIENTED_EDGE('',*,*,#887,.F.);
#1406=EDGE_LOOP('',(#1397,#1403,#1404,#1405));
#1407=FACE_BOUND('',#1406,.T.);
#1408=ADVANCED_FACE('F338',(#1396,#1407),#1385,.F.);
#1409=CARTESIAN_POINT('',(12.0717114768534,-10.498922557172,-7.02196379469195));
#1410=DIRECTION('',(0.,0.,1.));
#1411=DIRECTION('',(0.,-1.,0.));
#1412=AXIS2_PLACEMENT_3D('',#1409,#1410,#1411);
#1413=CYLINDRICAL_SURFACE('',#1412,7.99855153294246);
#1414=ORIENTED_EDGE('',*,*,#248,.F.);
#1415=ORIENTED_EDGE('',*,*,#142,.T.);
#1416=ORIENTED_EDGE('',*,*,#496,.F.);
#1417=ORIENTED_EDGE('',*,*,#1373,.T.);
#1418=ORIENTED_EDGE('',*,*,#937,.T.);
#1419=EDGE_LOOP('',(#1414,#1415,#1416,#1417,#1418));
#1420=FACE_BOUND('',#1419,.T.);
#1421=ADVANCED_FACE('F334',(#1420),#1413,.F.);
#1422=CARTESIAN_POINT('',(-12.0717114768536,-10.498922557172,-7.02196379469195));
#1423=DIRECTION('',(0.,0.,1.));
#1424=DIRECTION('',(0.,-1.,0.));
#1425=AXIS2_PLACEMENT_3D('',#1422,#1423,#1424);
#1426=CYLINDRICAL_SURFACE('',#1425,7.99855153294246);
#1427=ORIENTED_EDGE('',*,*,#317,.F.);
#1428=ORIENTED_EDGE('',*,*,#265,.T.);
#1429=ORIENTED_EDGE('',*,*,#1069,.F.);
#1430=ORIENTED_EDGE('',*,*,#1402,.F.);
#1431=ORIENTED_EDGE('',*,*,#1155,.T.);
#1432=EDGE_LOOP('',(#1427,#1428,#1429,#1430,#1431));
#1433=FACE_BOUND('',#1432,.T.);
#1434=ADVANCED_FACE('F337',(#1433),#1426,.F.);
#1435=CARTESIAN_POINT('',(17.2910340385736,-20.,19.5161101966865));
#1436=DIRECTION('',(0.,-1.,0.));
#1437=DIRECTION('',(1.,0.,0.));
#1438=AXIS2_PLACEMENT_3D('',#1435,#1436,#1437);
#1439=SPHERICAL_SURFACE('',#1438,17.955);
#1440=CARTESIAN_POINT('',(17.2910340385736,-20.,19.5161101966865));
#1441=DIRECTION('',(-0.101228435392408,-0.994863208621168,0.));
#1442=DIRECTION('',(0.994863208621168,-0.101228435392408,0.));
#1443=AXIS2_PLACEMENT_3D('',#1440,#1441,#1442);
#1444=SPHERICAL_SURFACE('',#1443,17.955);
#1445=ORIENTED_EDGE('',*,*,#1365,.T.);
#1446=EDGE_LOOP('',(#1445));
#1447=FACE_BOUND('',#1446,.T.);
#1448=ADVANCED_FACE('F238',(#1447),#1444,.F.);
#1449=CARTESIAN_POINT('',(17.2910340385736,20.,19.5161101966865));
#1450=DIRECTION('',(0.,1.,0.));
#1451=DIRECTION('',(1.,0.,0.));
#1452=AXIS2_PLACEMENT_3D('',#1449,#1450,#1451);
#1453=SPHERICAL_SURFACE('',#1452,17.955);
#1454=ORIENTED_EDGE('',*,*,#1341,.F.);
#1455=ORIENTED_EDGE('',*,*,#1247,.F.);
#1456=EDGE_LOOP('',(#1454,#1455));
#1457=FACE_BOUND('',#1456,.T.);
#1458=ADVANCED_FACE('F234',(#1457),#1453,.F.);
#1459=CARTESIAN_POINT('',(-17.2910340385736,-20.,19.5161101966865));
#1460=DIRECTION('',(0.,-1.,0.));
#1461=DIRECTION('',(-1.,0.,0.));
#1462=AXIS2_PLACEMENT_3D('',#1459,#1460,#1461);
#1463=SPHERICAL_SURFACE('',#1462,17.955);
#1464=CARTESIAN_POINT('',(-17.2910340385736,-20.,19.5161101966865));
#1465=DIRECTION('',(-0.101228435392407,0.994863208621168,0.));
#1466=DIRECTION('',(-0.994863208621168,-0.101228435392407,0.));
#1467=AXIS2_PLACEMENT_3D('',#1464,#1465,#1466);
#1468=SPHERICAL_SURFACE('',#1467,17.955);
#1469=ORIENTED_EDGE('',*,*,#1393,.F.);
#1470=EDGE_LOOP('',(#1469));
#1471=FACE_BOUND('',#1470,.T.);
#1472=ADVANCED_FACE('F231',(#1471),#1468,.F.);
#1473=CARTESIAN_POINT('',(-17.2910340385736,20.,19.5161101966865));
#1474=DIRECTION('',(0.,1.,0.));
#1475=DIRECTION('',(-1.,0.,0.));
#1476=AXIS2_PLACEMENT_3D('',#1473,#1474,#1475);
#1477=SPHERICAL_SURFACE('',#1476,17.955);
#1478=ORIENTED_EDGE('',*,*,#1281,.T.);
#1479=ORIENTED_EDGE('',*,*,#1310,.T.);
#1480=EDGE_LOOP('',(#1478,#1479));
#1481=FACE_BOUND('',#1480,.T.);
#1482=ADVANCED_FACE('F141',(#1481),#1477,.F.);
#1483=CLOSED_SHELL('',(#146,#196,#228,#275,#376,#500,#698,#891,#1074,#1088,#1105,#1117,#1226,
#1256,#1299,#1319,#1352,#1380,#1408,#1421,#1434,#1448,#1458,#1472,#1482));
#1484=MANIFOLD_SOLID_BREP('B1',#1483);
#1485=ADVANCED_BREP_SHAPE_REPRESENTATION('',(#18,#1484),#14);
#1486=SHAPE_DEFINITION_REPRESENTATION(#9,#1485);
ENDSEC;
END-ISO-10303-21;
